VERSION 5.8 ;
BUSBITCHARS "[]" ;
DIVIDERCHAR "/" ;
UNITS
    DATABASE MICRONS 1000 ;
END UNITS

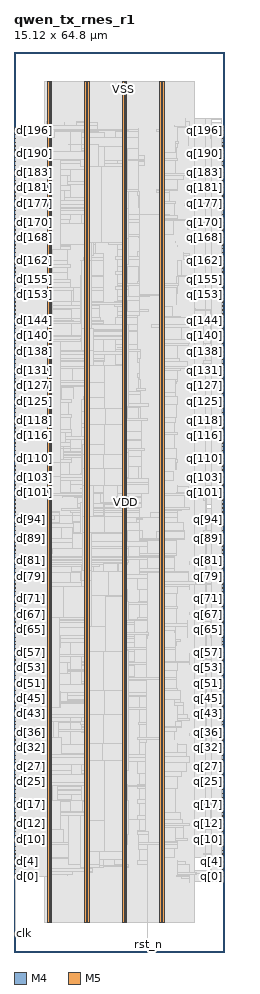
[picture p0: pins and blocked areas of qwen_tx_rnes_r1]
MACRO qwen_tx_rnes_r1
  FOREIGN qwen_tx_rnes_r1 0 0 ;
  CLASS BLOCK ;
  SIZE 15.12 BY 64.8 ;
  PIN clk
    DIRECTION INPUT ;
    USE SIGNAL ;
    PORT
      LAYER M4 ;
        RECT  0.054 1.296 0.138 1.32 ;
    END
    PORT
      LAYER M4 ;
        RECT  0.108 1.296 0.227 1.416 ;
    END
  END clk
  PIN d[0]
    DIRECTION INPUT ;
    USE SIGNAL ;
    PORT
      LAYER M4 ;
        RECT  0.054 5.424 0.138 5.448 ;
    END
  END d[0]
  PIN d[100]
    DIRECTION INPUT ;
    USE SIGNAL ;
    PORT
      LAYER M4 ;
        RECT  0.054 32.784 0.138 32.808 ;
    END
  END d[100]
  PIN d[101]
    DIRECTION INPUT ;
    USE SIGNAL ;
    PORT
      LAYER M4 ;
        RECT  0.054 33.072 0.138 33.096 ;
    END
  END d[101]
  PIN d[102]
    DIRECTION INPUT ;
    USE SIGNAL ;
    PORT
      LAYER M4 ;
        RECT  0.054 33.36 0.138 33.384 ;
    END
  END d[102]
  PIN d[103]
    DIRECTION INPUT ;
    USE SIGNAL ;
    PORT
      LAYER M4 ;
        RECT  0.054 33.6 0.138 33.624 ;
    END
  END d[103]
  PIN d[104]
    DIRECTION INPUT ;
    USE SIGNAL ;
    PORT
      LAYER M4 ;
        RECT  0.054 33.888 0.138 33.912 ;
    END
  END d[104]
  PIN d[105]
    DIRECTION INPUT ;
    USE SIGNAL ;
    PORT
      LAYER M4 ;
        RECT  0.054 34.176 0.138 34.2 ;
    END
  END d[105]
  PIN d[106]
    DIRECTION INPUT ;
    USE SIGNAL ;
    PORT
      LAYER M4 ;
        RECT  0.054 34.464 0.138 34.488 ;
    END
  END d[106]
  PIN d[107]
    DIRECTION INPUT ;
    USE SIGNAL ;
    PORT
      LAYER M4 ;
        RECT  0.054 34.704 0.138 34.728 ;
    END
  END d[107]
  PIN d[108]
    DIRECTION INPUT ;
    USE SIGNAL ;
    PORT
      LAYER M4 ;
        RECT  0.054 34.992 0.138 35.016 ;
    END
  END d[108]
  PIN d[109]
    DIRECTION INPUT ;
    USE SIGNAL ;
    PORT
      LAYER M4 ;
        RECT  0.054 35.28 0.138 35.304 ;
    END
  END d[109]
  PIN d[10]
    DIRECTION INPUT ;
    USE SIGNAL ;
    PORT
      LAYER M4 ;
        RECT  0.054 8.112 0.138 8.136 ;
    END
  END d[10]
  PIN d[110]
    DIRECTION INPUT ;
    USE SIGNAL ;
    PORT
      LAYER M4 ;
        RECT  0.054 35.52 0.138 35.544 ;
    END
  END d[110]
  PIN d[111]
    DIRECTION INPUT ;
    USE SIGNAL ;
    PORT
      LAYER M4 ;
        RECT  0.054 35.808 0.138 35.832 ;
    END
  END d[111]
  PIN d[112]
    DIRECTION INPUT ;
    USE SIGNAL ;
    PORT
      LAYER M4 ;
        RECT  0.054 36.096 0.138 36.12 ;
    END
  END d[112]
  PIN d[113]
    DIRECTION INPUT ;
    USE SIGNAL ;
    PORT
      LAYER M4 ;
        RECT  0.054 36.384 0.138 36.408 ;
    END
  END d[113]
  PIN d[114]
    DIRECTION INPUT ;
    USE SIGNAL ;
    PORT
      LAYER M4 ;
        RECT  0.054 36.624 0.138 36.648 ;
    END
  END d[114]
  PIN d[115]
    DIRECTION INPUT ;
    USE SIGNAL ;
    PORT
      LAYER M4 ;
        RECT  0.054 36.912 0.138 36.936 ;
    END
  END d[115]
  PIN d[116]
    DIRECTION INPUT ;
    USE SIGNAL ;
    PORT
      LAYER M4 ;
        RECT  0.054 37.2 0.138 37.224 ;
    END
  END d[116]
  PIN d[117]
    DIRECTION INPUT ;
    USE SIGNAL ;
    PORT
      LAYER M4 ;
        RECT  0.054 37.44 0.138 37.464 ;
    END
  END d[117]
  PIN d[118]
    DIRECTION INPUT ;
    USE SIGNAL ;
    PORT
      LAYER M4 ;
        RECT  0.054 37.728 0.138 37.752 ;
    END
  END d[118]
  PIN d[119]
    DIRECTION INPUT ;
    USE SIGNAL ;
    PORT
      LAYER M4 ;
        RECT  0.054 38.016 0.138 38.04 ;
    END
  END d[119]
  PIN d[11]
    DIRECTION INPUT ;
    USE SIGNAL ;
    PORT
      LAYER M4 ;
        RECT  0.054 8.4 0.138 8.424 ;
    END
  END d[11]
  PIN d[120]
    DIRECTION INPUT ;
    USE SIGNAL ;
    PORT
      LAYER M4 ;
        RECT  0.054 38.304 0.138 38.328 ;
    END
  END d[120]
  PIN d[121]
    DIRECTION INPUT ;
    USE SIGNAL ;
    PORT
      LAYER M4 ;
        RECT  0.054 38.544 0.138 38.568 ;
    END
  END d[121]
  PIN d[122]
    DIRECTION INPUT ;
    USE SIGNAL ;
    PORT
      LAYER M4 ;
        RECT  0.054 38.832 0.138 38.856 ;
    END
  END d[122]
  PIN d[123]
    DIRECTION INPUT ;
    USE SIGNAL ;
    PORT
      LAYER M4 ;
        RECT  0.054 39.12 0.138 39.144 ;
    END
  END d[123]
  PIN d[124]
    DIRECTION INPUT ;
    USE SIGNAL ;
    PORT
      LAYER M4 ;
        RECT  0.054 39.36 0.138 39.384 ;
    END
  END d[124]
  PIN d[125]
    DIRECTION INPUT ;
    USE SIGNAL ;
    PORT
      LAYER M4 ;
        RECT  0.054 39.648 0.138 39.672 ;
    END
  END d[125]
  PIN d[126]
    DIRECTION INPUT ;
    USE SIGNAL ;
    PORT
      LAYER M4 ;
        RECT  0.054 39.936 0.138 39.96 ;
    END
  END d[126]
  PIN d[127]
    DIRECTION INPUT ;
    USE SIGNAL ;
    PORT
      LAYER M4 ;
        RECT  0.054 40.224 0.138 40.248 ;
    END
  END d[127]
  PIN d[128]
    DIRECTION INPUT ;
    USE SIGNAL ;
    PORT
      LAYER M4 ;
        RECT  0.054 40.464 0.138 40.488 ;
    END
  END d[128]
  PIN d[129]
    DIRECTION INPUT ;
    USE SIGNAL ;
    PORT
      LAYER M4 ;
        RECT  0.054 40.752 0.138 40.776 ;
    END
  END d[129]
  PIN d[12]
    DIRECTION INPUT ;
    USE SIGNAL ;
    PORT
      LAYER M4 ;
        RECT  0.054 8.688 0.138 8.712 ;
    END
  END d[12]
  PIN d[130]
    DIRECTION INPUT ;
    USE SIGNAL ;
    PORT
      LAYER M4 ;
        RECT  0.054 41.04 0.138 41.064 ;
    END
  END d[130]
  PIN d[131]
    DIRECTION INPUT ;
    USE SIGNAL ;
    PORT
      LAYER M4 ;
        RECT  0.054 41.28 0.138 41.304 ;
    END
  END d[131]
  PIN d[132]
    DIRECTION INPUT ;
    USE SIGNAL ;
    PORT
      LAYER M4 ;
        RECT  0.054 41.568 0.138 41.592 ;
    END
  END d[132]
  PIN d[133]
    DIRECTION INPUT ;
    USE SIGNAL ;
    PORT
      LAYER M4 ;
        RECT  0.054 41.856 0.138 41.88 ;
    END
  END d[133]
  PIN d[134]
    DIRECTION INPUT ;
    USE SIGNAL ;
    PORT
      LAYER M4 ;
        RECT  0.054 42.096 0.138 42.12 ;
    END
  END d[134]
  PIN d[135]
    DIRECTION INPUT ;
    USE SIGNAL ;
    PORT
      LAYER M4 ;
        RECT  0.054 42.384 0.138 42.408 ;
    END
  END d[135]
  PIN d[136]
    DIRECTION INPUT ;
    USE SIGNAL ;
    PORT
      LAYER M4 ;
        RECT  0.054 42.672 0.138 42.696 ;
    END
  END d[136]
  PIN d[137]
    DIRECTION INPUT ;
    USE SIGNAL ;
    PORT
      LAYER M4 ;
        RECT  0.054 42.96 0.138 42.984 ;
    END
  END d[137]
  PIN d[138]
    DIRECTION INPUT ;
    USE SIGNAL ;
    PORT
      LAYER M4 ;
        RECT  0.054 43.2 0.138 43.224 ;
    END
  END d[138]
  PIN d[139]
    DIRECTION INPUT ;
    USE SIGNAL ;
    PORT
      LAYER M4 ;
        RECT  0.054 43.488 0.138 43.512 ;
    END
  END d[139]
  PIN d[13]
    DIRECTION INPUT ;
    USE SIGNAL ;
    PORT
      LAYER M4 ;
        RECT  0.054 8.928 0.138 8.952 ;
    END
  END d[13]
  PIN d[140]
    DIRECTION INPUT ;
    USE SIGNAL ;
    PORT
      LAYER M4 ;
        RECT  0.054 43.776 0.138 43.8 ;
    END
  END d[140]
  PIN d[141]
    DIRECTION INPUT ;
    USE SIGNAL ;
    PORT
      LAYER M4 ;
        RECT  0.054 44.016 0.138 44.04 ;
    END
  END d[141]
  PIN d[142]
    DIRECTION INPUT ;
    USE SIGNAL ;
    PORT
      LAYER M4 ;
        RECT  0.054 44.304 0.138 44.328 ;
    END
  END d[142]
  PIN d[143]
    DIRECTION INPUT ;
    USE SIGNAL ;
    PORT
      LAYER M4 ;
        RECT  0.054 44.592 0.138 44.616 ;
    END
  END d[143]
  PIN d[144]
    DIRECTION INPUT ;
    USE SIGNAL ;
    PORT
      LAYER M4 ;
        RECT  0.054 44.88 0.138 44.904 ;
    END
  END d[144]
  PIN d[145]
    DIRECTION INPUT ;
    USE SIGNAL ;
    PORT
      LAYER M4 ;
        RECT  0.054 45.12 0.138 45.144 ;
    END
  END d[145]
  PIN d[146]
    DIRECTION INPUT ;
    USE SIGNAL ;
    PORT
      LAYER M4 ;
        RECT  0.054 45.408 0.138 45.432 ;
    END
  END d[146]
  PIN d[147]
    DIRECTION INPUT ;
    USE SIGNAL ;
    PORT
      LAYER M4 ;
        RECT  0.054 45.696 0.138 45.72 ;
    END
  END d[147]
  PIN d[148]
    DIRECTION INPUT ;
    USE SIGNAL ;
    PORT
      LAYER M4 ;
        RECT  0.054 45.936 0.138 45.96 ;
    END
  END d[148]
  PIN d[149]
    DIRECTION INPUT ;
    USE SIGNAL ;
    PORT
      LAYER M4 ;
        RECT  0.054 46.224 0.138 46.248 ;
    END
  END d[149]
  PIN d[14]
    DIRECTION INPUT ;
    USE SIGNAL ;
    PORT
      LAYER M4 ;
        RECT  0.054 9.216 0.138 9.24 ;
    END
  END d[14]
  PIN d[150]
    DIRECTION INPUT ;
    USE SIGNAL ;
    PORT
      LAYER M4 ;
        RECT  0.054 46.512 0.138 46.536 ;
    END
  END d[150]
  PIN d[151]
    DIRECTION INPUT ;
    USE SIGNAL ;
    PORT
      LAYER M4 ;
        RECT  0.054 46.8 0.138 46.824 ;
    END
  END d[151]
  PIN d[152]
    DIRECTION INPUT ;
    USE SIGNAL ;
    PORT
      LAYER M4 ;
        RECT  0.054 47.04 0.138 47.064 ;
    END
  END d[152]
  PIN d[153]
    DIRECTION INPUT ;
    USE SIGNAL ;
    PORT
      LAYER M4 ;
        RECT  0.054 47.328 0.138 47.352 ;
    END
  END d[153]
  PIN d[154]
    DIRECTION INPUT ;
    USE SIGNAL ;
    PORT
      LAYER M4 ;
        RECT  0.054 47.616 0.138 47.64 ;
    END
  END d[154]
  PIN d[155]
    DIRECTION INPUT ;
    USE SIGNAL ;
    PORT
      LAYER M4 ;
        RECT  0.054 47.856 0.138 47.88 ;
    END
  END d[155]
  PIN d[156]
    DIRECTION INPUT ;
    USE SIGNAL ;
    PORT
      LAYER M4 ;
        RECT  0.054 48.144 0.138 48.168 ;
    END
  END d[156]
  PIN d[157]
    DIRECTION INPUT ;
    USE SIGNAL ;
    PORT
      LAYER M4 ;
        RECT  0.054 48.432 0.138 48.456 ;
    END
  END d[157]
  PIN d[158]
    DIRECTION INPUT ;
    USE SIGNAL ;
    PORT
      LAYER M4 ;
        RECT  0.054 48.72 0.138 48.744 ;
    END
  END d[158]
  PIN d[159]
    DIRECTION INPUT ;
    USE SIGNAL ;
    PORT
      LAYER M4 ;
        RECT  0.054 48.96 0.138 48.984 ;
    END
  END d[159]
  PIN d[15]
    DIRECTION INPUT ;
    USE SIGNAL ;
    PORT
      LAYER M4 ;
        RECT  0.054 9.504 0.138 9.528 ;
    END
  END d[15]
  PIN d[160]
    DIRECTION INPUT ;
    USE SIGNAL ;
    PORT
      LAYER M4 ;
        RECT  0.054 49.248 0.138 49.272 ;
    END
  END d[160]
  PIN d[161]
    DIRECTION INPUT ;
    USE SIGNAL ;
    PORT
      LAYER M4 ;
        RECT  0.054 49.536 0.138 49.56 ;
    END
  END d[161]
  PIN d[162]
    DIRECTION INPUT ;
    USE SIGNAL ;
    PORT
      LAYER M4 ;
        RECT  0.054 49.776 0.138 49.8 ;
    END
  END d[162]
  PIN d[163]
    DIRECTION INPUT ;
    USE SIGNAL ;
    PORT
      LAYER M4 ;
        RECT  0.054 50.064 0.138 50.088 ;
    END
  END d[163]
  PIN d[164]
    DIRECTION INPUT ;
    USE SIGNAL ;
    PORT
      LAYER M4 ;
        RECT  0.054 50.352 0.138 50.376 ;
    END
  END d[164]
  PIN d[165]
    DIRECTION INPUT ;
    USE SIGNAL ;
    PORT
      LAYER M4 ;
        RECT  0.054 50.64 0.138 50.664 ;
    END
  END d[165]
  PIN d[166]
    DIRECTION INPUT ;
    USE SIGNAL ;
    PORT
      LAYER M4 ;
        RECT  0.054 50.88 0.138 50.904 ;
    END
  END d[166]
  PIN d[167]
    DIRECTION INPUT ;
    USE SIGNAL ;
    PORT
      LAYER M4 ;
        RECT  0.054 51.168 0.138 51.192 ;
    END
  END d[167]
  PIN d[168]
    DIRECTION INPUT ;
    USE SIGNAL ;
    PORT
      LAYER M4 ;
        RECT  0.054 51.456 0.138 51.48 ;
    END
  END d[168]
  PIN d[169]
    DIRECTION INPUT ;
    USE SIGNAL ;
    PORT
      LAYER M4 ;
        RECT  0.054 51.696 0.138 51.72 ;
    END
  END d[169]
  PIN d[16]
    DIRECTION INPUT ;
    USE SIGNAL ;
    PORT
      LAYER M4 ;
        RECT  0.054 9.792 0.138 9.816 ;
    END
  END d[16]
  PIN d[170]
    DIRECTION INPUT ;
    USE SIGNAL ;
    PORT
      LAYER M4 ;
        RECT  0.054 51.984 0.138 52.008 ;
    END
  END d[170]
  PIN d[171]
    DIRECTION INPUT ;
    USE SIGNAL ;
    PORT
      LAYER M4 ;
        RECT  0.054 52.272 0.138 52.296 ;
    END
  END d[171]
  PIN d[172]
    DIRECTION INPUT ;
    USE SIGNAL ;
    PORT
      LAYER M4 ;
        RECT  0.054 52.512 0.138 52.536 ;
    END
  END d[172]
  PIN d[173]
    DIRECTION INPUT ;
    USE SIGNAL ;
    PORT
      LAYER M4 ;
        RECT  0.054 52.8 0.138 52.824 ;
    END
  END d[173]
  PIN d[174]
    DIRECTION INPUT ;
    USE SIGNAL ;
    PORT
      LAYER M4 ;
        RECT  0.054 53.088 0.138 53.112 ;
    END
  END d[174]
  PIN d[175]
    DIRECTION INPUT ;
    USE SIGNAL ;
    PORT
      LAYER M4 ;
        RECT  0.054 53.376 0.138 53.4 ;
    END
  END d[175]
  PIN d[176]
    DIRECTION INPUT ;
    USE SIGNAL ;
    PORT
      LAYER M4 ;
        RECT  0.054 53.616 0.138 53.64 ;
    END
  END d[176]
  PIN d[177]
    DIRECTION INPUT ;
    USE SIGNAL ;
    PORT
      LAYER M4 ;
        RECT  0.054 53.904 0.138 53.928 ;
    END
  END d[177]
  PIN d[178]
    DIRECTION INPUT ;
    USE SIGNAL ;
    PORT
      LAYER M4 ;
        RECT  0.054 54.192 0.138 54.216 ;
    END
  END d[178]
  PIN d[179]
    DIRECTION INPUT ;
    USE SIGNAL ;
    PORT
      LAYER M4 ;
        RECT  0.054 54.432 0.138 54.456 ;
    END
  END d[179]
  PIN d[17]
    DIRECTION INPUT ;
    USE SIGNAL ;
    PORT
      LAYER M4 ;
        RECT  0.054 10.032 0.138 10.056 ;
    END
  END d[17]
  PIN d[180]
    DIRECTION INPUT ;
    USE SIGNAL ;
    PORT
      LAYER M4 ;
        RECT  0.054 54.72 0.138 54.744 ;
    END
  END d[180]
  PIN d[181]
    DIRECTION INPUT ;
    USE SIGNAL ;
    PORT
      LAYER M4 ;
        RECT  0.054 55.008 0.138 55.032 ;
    END
  END d[181]
  PIN d[182]
    DIRECTION INPUT ;
    USE SIGNAL ;
    PORT
      LAYER M4 ;
        RECT  0.054 55.296 0.138 55.32 ;
    END
  END d[182]
  PIN d[183]
    DIRECTION INPUT ;
    USE SIGNAL ;
    PORT
      LAYER M4 ;
        RECT  0.054 55.536 0.138 55.56 ;
    END
  END d[183]
  PIN d[184]
    DIRECTION INPUT ;
    USE SIGNAL ;
    PORT
      LAYER M4 ;
        RECT  0.054 55.824 0.138 55.848 ;
    END
  END d[184]
  PIN d[185]
    DIRECTION INPUT ;
    USE SIGNAL ;
    PORT
      LAYER M4 ;
        RECT  0.054 56.112 0.138 56.136 ;
    END
  END d[185]
  PIN d[186]
    DIRECTION INPUT ;
    USE SIGNAL ;
    PORT
      LAYER M4 ;
        RECT  0.054 56.352 0.138 56.376 ;
    END
  END d[186]
  PIN d[187]
    DIRECTION INPUT ;
    USE SIGNAL ;
    PORT
      LAYER M4 ;
        RECT  0.054 56.64 0.138 56.664 ;
    END
  END d[187]
  PIN d[188]
    DIRECTION INPUT ;
    USE SIGNAL ;
    PORT
      LAYER M4 ;
        RECT  0.054 56.928 0.138 56.952 ;
    END
  END d[188]
  PIN d[189]
    DIRECTION INPUT ;
    USE SIGNAL ;
    PORT
      LAYER M4 ;
        RECT  0.054 57.216 0.138 57.24 ;
    END
  END d[189]
  PIN d[18]
    DIRECTION INPUT ;
    USE SIGNAL ;
    PORT
      LAYER M4 ;
        RECT  0.054 10.32 0.138 10.344 ;
    END
  END d[18]
  PIN d[190]
    DIRECTION INPUT ;
    USE SIGNAL ;
    PORT
      LAYER M4 ;
        RECT  0.054 57.456 0.138 57.48 ;
    END
  END d[190]
  PIN d[191]
    DIRECTION INPUT ;
    USE SIGNAL ;
    PORT
      LAYER M4 ;
        RECT  0.054 57.744 0.138 57.768 ;
    END
  END d[191]
  PIN d[192]
    DIRECTION INPUT ;
    USE SIGNAL ;
    PORT
      LAYER M4 ;
        RECT  0.054 58.032 0.138 58.056 ;
    END
  END d[192]
  PIN d[193]
    DIRECTION INPUT ;
    USE SIGNAL ;
    PORT
      LAYER M4 ;
        RECT  0.054 58.272 0.138 58.296 ;
    END
  END d[193]
  PIN d[194]
    DIRECTION INPUT ;
    USE SIGNAL ;
    PORT
      LAYER M4 ;
        RECT  0.054 58.56 0.138 58.584 ;
    END
  END d[194]
  PIN d[195]
    DIRECTION INPUT ;
    USE SIGNAL ;
    PORT
      LAYER M4 ;
        RECT  0.054 58.848 0.138 58.872 ;
    END
  END d[195]
  PIN d[196]
    DIRECTION INPUT ;
    USE SIGNAL ;
    PORT
      LAYER M4 ;
        RECT  0.054 59.136 0.138 59.16 ;
    END
  END d[196]
  PIN d[197]
    DIRECTION INPUT ;
    USE SIGNAL ;
    PORT
      LAYER M4 ;
        RECT  0.054 59.376 0.138 59.4 ;
    END
  END d[197]
  PIN d[19]
    DIRECTION INPUT ;
    USE SIGNAL ;
    PORT
      LAYER M4 ;
        RECT  0.054 10.608 0.138 10.632 ;
    END
  END d[19]
  PIN d[1]
    DIRECTION INPUT ;
    USE SIGNAL ;
    PORT
      LAYER M4 ;
        RECT  0.054 5.664 0.138 5.688 ;
    END
  END d[1]
  PIN d[20]
    DIRECTION INPUT ;
    USE SIGNAL ;
    PORT
      LAYER M4 ;
        RECT  0.054 10.848 0.138 10.872 ;
    END
  END d[20]
  PIN d[21]
    DIRECTION INPUT ;
    USE SIGNAL ;
    PORT
      LAYER M4 ;
        RECT  0.054 11.136 0.138 11.16 ;
    END
  END d[21]
  PIN d[22]
    DIRECTION INPUT ;
    USE SIGNAL ;
    PORT
      LAYER M4 ;
        RECT  0.054 11.424 0.138 11.448 ;
    END
  END d[22]
  PIN d[23]
    DIRECTION INPUT ;
    USE SIGNAL ;
    PORT
      LAYER M4 ;
        RECT  0.054 11.712 0.138 11.736 ;
    END
  END d[23]
  PIN d[24]
    DIRECTION INPUT ;
    USE SIGNAL ;
    PORT
      LAYER M4 ;
        RECT  0.054 11.952 0.138 11.976 ;
    END
  END d[24]
  PIN d[25]
    DIRECTION INPUT ;
    USE SIGNAL ;
    PORT
      LAYER M4 ;
        RECT  0.054 12.24 0.138 12.264 ;
    END
  END d[25]
  PIN d[26]
    DIRECTION INPUT ;
    USE SIGNAL ;
    PORT
      LAYER M4 ;
        RECT  0.054 12.528 0.138 12.552 ;
    END
  END d[26]
  PIN d[27]
    DIRECTION INPUT ;
    USE SIGNAL ;
    PORT
      LAYER M4 ;
        RECT  0.054 12.768 0.138 12.792 ;
    END
  END d[27]
  PIN d[28]
    DIRECTION INPUT ;
    USE SIGNAL ;
    PORT
      LAYER M4 ;
        RECT  0.054 13.056 0.138 13.08 ;
    END
  END d[28]
  PIN d[29]
    DIRECTION INPUT ;
    USE SIGNAL ;
    PORT
      LAYER M4 ;
        RECT  0.054 13.344 0.138 13.368 ;
    END
  END d[29]
  PIN d[2]
    DIRECTION INPUT ;
    USE SIGNAL ;
    PORT
      LAYER M4 ;
        RECT  0.054 5.952 0.138 5.976 ;
    END
  END d[2]
  PIN d[30]
    DIRECTION INPUT ;
    USE SIGNAL ;
    PORT
      LAYER M4 ;
        RECT  0.054 13.632 0.138 13.656 ;
    END
  END d[30]
  PIN d[31]
    DIRECTION INPUT ;
    USE SIGNAL ;
    PORT
      LAYER M4 ;
        RECT  0.054 13.872 0.138 13.896 ;
    END
  END d[31]
  PIN d[32]
    DIRECTION INPUT ;
    USE SIGNAL ;
    PORT
      LAYER M4 ;
        RECT  0.054 14.16 0.138 14.184 ;
    END
  END d[32]
  PIN d[33]
    DIRECTION INPUT ;
    USE SIGNAL ;
    PORT
      LAYER M4 ;
        RECT  0.054 14.448 0.138 14.472 ;
    END
  END d[33]
  PIN d[34]
    DIRECTION INPUT ;
    USE SIGNAL ;
    PORT
      LAYER M4 ;
        RECT  0.054 14.688 0.138 14.712 ;
    END
  END d[34]
  PIN d[35]
    DIRECTION INPUT ;
    USE SIGNAL ;
    PORT
      LAYER M4 ;
        RECT  0.054 14.976 0.138 15 ;
    END
  END d[35]
  PIN d[36]
    DIRECTION INPUT ;
    USE SIGNAL ;
    PORT
      LAYER M4 ;
        RECT  0.054 15.264 0.138 15.288 ;
    END
  END d[36]
  PIN d[37]
    DIRECTION INPUT ;
    USE SIGNAL ;
    PORT
      LAYER M4 ;
        RECT  0.054 15.552 0.138 15.576 ;
    END
  END d[37]
  PIN d[38]
    DIRECTION INPUT ;
    USE SIGNAL ;
    PORT
      LAYER M4 ;
        RECT  0.054 15.792 0.138 15.816 ;
    END
  END d[38]
  PIN d[39]
    DIRECTION INPUT ;
    USE SIGNAL ;
    PORT
      LAYER M4 ;
        RECT  0.054 16.08 0.138 16.104 ;
    END
  END d[39]
  PIN d[3]
    DIRECTION INPUT ;
    USE SIGNAL ;
    PORT
      LAYER M4 ;
        RECT  0.054 6.192 0.138 6.216 ;
    END
  END d[3]
  PIN d[40]
    DIRECTION INPUT ;
    USE SIGNAL ;
    PORT
      LAYER M4 ;
        RECT  0.054 16.368 0.138 16.392 ;
    END
  END d[40]
  PIN d[41]
    DIRECTION INPUT ;
    USE SIGNAL ;
    PORT
      LAYER M4 ;
        RECT  0.054 16.608 0.138 16.632 ;
    END
  END d[41]
  PIN d[42]
    DIRECTION INPUT ;
    USE SIGNAL ;
    PORT
      LAYER M4 ;
        RECT  0.054 16.896 0.138 16.92 ;
    END
  END d[42]
  PIN d[43]
    DIRECTION INPUT ;
    USE SIGNAL ;
    PORT
      LAYER M4 ;
        RECT  0.054 17.184 0.138 17.208 ;
    END
  END d[43]
  PIN d[44]
    DIRECTION INPUT ;
    USE SIGNAL ;
    PORT
      LAYER M4 ;
        RECT  0.054 17.472 0.138 17.496 ;
    END
  END d[44]
  PIN d[45]
    DIRECTION INPUT ;
    USE SIGNAL ;
    PORT
      LAYER M4 ;
        RECT  0.054 17.712 0.138 17.736 ;
    END
  END d[45]
  PIN d[46]
    DIRECTION INPUT ;
    USE SIGNAL ;
    PORT
      LAYER M4 ;
        RECT  0.054 18 0.138 18.024 ;
    END
  END d[46]
  PIN d[47]
    DIRECTION INPUT ;
    USE SIGNAL ;
    PORT
      LAYER M4 ;
        RECT  0.054 18.288 0.138 18.312 ;
    END
  END d[47]
  PIN d[48]
    DIRECTION INPUT ;
    USE SIGNAL ;
    PORT
      LAYER M4 ;
        RECT  0.054 18.528 0.138 18.552 ;
    END
  END d[48]
  PIN d[49]
    DIRECTION INPUT ;
    USE SIGNAL ;
    PORT
      LAYER M4 ;
        RECT  0.054 18.816 0.138 18.84 ;
    END
  END d[49]
  PIN d[4]
    DIRECTION INPUT ;
    USE SIGNAL ;
    PORT
      LAYER M4 ;
        RECT  0.054 6.48 0.138 6.504 ;
    END
  END d[4]
  PIN d[50]
    DIRECTION INPUT ;
    USE SIGNAL ;
    PORT
      LAYER M4 ;
        RECT  0.054 19.104 0.138 19.128 ;
    END
  END d[50]
  PIN d[51]
    DIRECTION INPUT ;
    USE SIGNAL ;
    PORT
      LAYER M4 ;
        RECT  0.054 19.344 0.138 19.368 ;
    END
  END d[51]
  PIN d[52]
    DIRECTION INPUT ;
    USE SIGNAL ;
    PORT
      LAYER M4 ;
        RECT  0.054 19.632 0.138 19.656 ;
    END
  END d[52]
  PIN d[53]
    DIRECTION INPUT ;
    USE SIGNAL ;
    PORT
      LAYER M4 ;
        RECT  0.054 19.92 0.138 19.944 ;
    END
  END d[53]
  PIN d[54]
    DIRECTION INPUT ;
    USE SIGNAL ;
    PORT
      LAYER M4 ;
        RECT  0.054 20.208 0.138 20.232 ;
    END
  END d[54]
  PIN d[55]
    DIRECTION INPUT ;
    USE SIGNAL ;
    PORT
      LAYER M4 ;
        RECT  0.054 20.448 0.138 20.472 ;
    END
  END d[55]
  PIN d[56]
    DIRECTION INPUT ;
    USE SIGNAL ;
    PORT
      LAYER M4 ;
        RECT  0.054 20.736 0.138 20.76 ;
    END
  END d[56]
  PIN d[57]
    DIRECTION INPUT ;
    USE SIGNAL ;
    PORT
      LAYER M4 ;
        RECT  0.054 21.024 0.138 21.048 ;
    END
  END d[57]
  PIN d[58]
    DIRECTION INPUT ;
    USE SIGNAL ;
    PORT
      LAYER M4 ;
        RECT  0.054 21.264 0.138 21.288 ;
    END
  END d[58]
  PIN d[59]
    DIRECTION INPUT ;
    USE SIGNAL ;
    PORT
      LAYER M4 ;
        RECT  0.054 21.552 0.138 21.576 ;
    END
  END d[59]
  PIN d[5]
    DIRECTION INPUT ;
    USE SIGNAL ;
    PORT
      LAYER M4 ;
        RECT  0.054 6.768 0.138 6.792 ;
    END
  END d[5]
  PIN d[60]
    DIRECTION INPUT ;
    USE SIGNAL ;
    PORT
      LAYER M4 ;
        RECT  0.054 21.84 0.138 21.864 ;
    END
  END d[60]
  PIN d[61]
    DIRECTION INPUT ;
    USE SIGNAL ;
    PORT
      LAYER M4 ;
        RECT  0.054 22.128 0.138 22.152 ;
    END
  END d[61]
  PIN d[62]
    DIRECTION INPUT ;
    USE SIGNAL ;
    PORT
      LAYER M4 ;
        RECT  0.054 22.368 0.138 22.392 ;
    END
  END d[62]
  PIN d[63]
    DIRECTION INPUT ;
    USE SIGNAL ;
    PORT
      LAYER M4 ;
        RECT  0.054 22.656 0.138 22.68 ;
    END
  END d[63]
  PIN d[64]
    DIRECTION INPUT ;
    USE SIGNAL ;
    PORT
      LAYER M4 ;
        RECT  0.054 22.944 0.138 22.968 ;
    END
  END d[64]
  PIN d[65]
    DIRECTION INPUT ;
    USE SIGNAL ;
    PORT
      LAYER M4 ;
        RECT  0.054 23.184 0.138 23.208 ;
    END
  END d[65]
  PIN d[66]
    DIRECTION INPUT ;
    USE SIGNAL ;
    PORT
      LAYER M4 ;
        RECT  0.054 23.472 0.138 23.496 ;
    END
  END d[66]
  PIN d[67]
    DIRECTION INPUT ;
    USE SIGNAL ;
    PORT
      LAYER M4 ;
        RECT  0.054 23.76 0.138 23.784 ;
    END
  END d[67]
  PIN d[68]
    DIRECTION INPUT ;
    USE SIGNAL ;
    PORT
      LAYER M4 ;
        RECT  0.054 24.048 0.138 24.072 ;
    END
  END d[68]
  PIN d[69]
    DIRECTION INPUT ;
    USE SIGNAL ;
    PORT
      LAYER M4 ;
        RECT  0.054 24.288 0.138 24.312 ;
    END
  END d[69]
  PIN d[6]
    DIRECTION INPUT ;
    USE SIGNAL ;
    PORT
      LAYER M4 ;
        RECT  0.054 7.056 0.138 7.08 ;
    END
  END d[6]
  PIN d[70]
    DIRECTION INPUT ;
    USE SIGNAL ;
    PORT
      LAYER M4 ;
        RECT  0.054 24.576 0.138 24.6 ;
    END
  END d[70]
  PIN d[71]
    DIRECTION INPUT ;
    USE SIGNAL ;
    PORT
      LAYER M4 ;
        RECT  0.054 24.864 0.138 24.888 ;
    END
  END d[71]
  PIN d[72]
    DIRECTION INPUT ;
    USE SIGNAL ;
    PORT
      LAYER M4 ;
        RECT  0.054 25.104 0.138 25.128 ;
    END
  END d[72]
  PIN d[73]
    DIRECTION INPUT ;
    USE SIGNAL ;
    PORT
      LAYER M4 ;
        RECT  0.054 25.392 0.138 25.416 ;
    END
  END d[73]
  PIN d[74]
    DIRECTION INPUT ;
    USE SIGNAL ;
    PORT
      LAYER M4 ;
        RECT  0.054 25.68 0.138 25.704 ;
    END
  END d[74]
  PIN d[75]
    DIRECTION INPUT ;
    USE SIGNAL ;
    PORT
      LAYER M4 ;
        RECT  0.054 25.968 0.138 25.992 ;
    END
  END d[75]
  PIN d[76]
    DIRECTION INPUT ;
    USE SIGNAL ;
    PORT
      LAYER M4 ;
        RECT  0.054 26.208 0.138 26.232 ;
    END
  END d[76]
  PIN d[77]
    DIRECTION INPUT ;
    USE SIGNAL ;
    PORT
      LAYER M4 ;
        RECT  0.054 26.496 0.138 26.52 ;
    END
  END d[77]
  PIN d[78]
    DIRECTION INPUT ;
    USE SIGNAL ;
    PORT
      LAYER M4 ;
        RECT  0.054 26.784 0.138 26.808 ;
    END
  END d[78]
  PIN d[79]
    DIRECTION INPUT ;
    USE SIGNAL ;
    PORT
      LAYER M4 ;
        RECT  0.054 27.024 0.138 27.048 ;
    END
  END d[79]
  PIN d[7]
    DIRECTION INPUT ;
    USE SIGNAL ;
    PORT
      LAYER M4 ;
        RECT  0.054 7.296 0.138 7.32 ;
    END
  END d[7]
  PIN d[80]
    DIRECTION INPUT ;
    USE SIGNAL ;
    PORT
      LAYER M4 ;
        RECT  0.054 27.312 0.138 27.336 ;
    END
  END d[80]
  PIN d[81]
    DIRECTION INPUT ;
    USE SIGNAL ;
    PORT
      LAYER M4 ;
        RECT  0.054 27.6 0.138 27.624 ;
    END
  END d[81]
  PIN d[82]
    DIRECTION INPUT ;
    USE SIGNAL ;
    PORT
      LAYER M4 ;
        RECT  0.054 27.888 0.138 27.912 ;
    END
  END d[82]
  PIN d[83]
    DIRECTION INPUT ;
    USE SIGNAL ;
    PORT
      LAYER M4 ;
        RECT  0.054 28.128 0.138 28.152 ;
    END
  END d[83]
  PIN d[84]
    DIRECTION INPUT ;
    USE SIGNAL ;
    PORT
      LAYER M4 ;
        RECT  0.054 28.416 0.138 28.44 ;
    END
  END d[84]
  PIN d[85]
    DIRECTION INPUT ;
    USE SIGNAL ;
    PORT
      LAYER M4 ;
        RECT  0.054 28.704 0.138 28.728 ;
    END
  END d[85]
  PIN d[86]
    DIRECTION INPUT ;
    USE SIGNAL ;
    PORT
      LAYER M4 ;
        RECT  0.054 28.944 0.138 28.968 ;
    END
  END d[86]
  PIN d[87]
    DIRECTION INPUT ;
    USE SIGNAL ;
    PORT
      LAYER M4 ;
        RECT  0.054 29.232 0.138 29.256 ;
    END
  END d[87]
  PIN d[88]
    DIRECTION INPUT ;
    USE SIGNAL ;
    PORT
      LAYER M4 ;
        RECT  0.054 29.52 0.138 29.544 ;
    END
  END d[88]
  PIN d[89]
    DIRECTION INPUT ;
    USE SIGNAL ;
    PORT
      LAYER M4 ;
        RECT  0.054 29.76 0.138 29.784 ;
    END
  END d[89]
  PIN d[8]
    DIRECTION INPUT ;
    USE SIGNAL ;
    PORT
      LAYER M4 ;
        RECT  0.054 7.584 0.138 7.608 ;
    END
  END d[8]
  PIN d[90]
    DIRECTION INPUT ;
    USE SIGNAL ;
    PORT
      LAYER M4 ;
        RECT  0.054 30.048 0.138 30.072 ;
    END
  END d[90]
  PIN d[91]
    DIRECTION INPUT ;
    USE SIGNAL ;
    PORT
      LAYER M4 ;
        RECT  0.054 30.336 0.138 30.36 ;
    END
  END d[91]
  PIN d[92]
    DIRECTION INPUT ;
    USE SIGNAL ;
    PORT
      LAYER M4 ;
        RECT  0.054 30.624 0.138 30.648 ;
    END
  END d[92]
  PIN d[93]
    DIRECTION INPUT ;
    USE SIGNAL ;
    PORT
      LAYER M4 ;
        RECT  0.054 30.864 0.138 30.888 ;
    END
  END d[93]
  PIN d[94]
    DIRECTION INPUT ;
    USE SIGNAL ;
    PORT
      LAYER M4 ;
        RECT  0.054 31.152 0.138 31.176 ;
    END
  END d[94]
  PIN d[95]
    DIRECTION INPUT ;
    USE SIGNAL ;
    PORT
      LAYER M4 ;
        RECT  0.054 31.44 0.138 31.464 ;
    END
  END d[95]
  PIN d[96]
    DIRECTION INPUT ;
    USE SIGNAL ;
    PORT
      LAYER M4 ;
        RECT  0.054 31.68 0.138 31.704 ;
    END
  END d[96]
  PIN d[97]
    DIRECTION INPUT ;
    USE SIGNAL ;
    PORT
      LAYER M4 ;
        RECT  0.054 31.968 0.138 31.992 ;
    END
  END d[97]
  PIN d[98]
    DIRECTION INPUT ;
    USE SIGNAL ;
    PORT
      LAYER M4 ;
        RECT  0.054 32.256 0.138 32.28 ;
    END
  END d[98]
  PIN d[99]
    DIRECTION INPUT ;
    USE SIGNAL ;
    PORT
      LAYER M4 ;
        RECT  0.054 32.544 0.138 32.568 ;
    END
  END d[99]
  PIN d[9]
    DIRECTION INPUT ;
    USE SIGNAL ;
    PORT
      LAYER M4 ;
        RECT  0.054 7.872 0.138 7.896 ;
    END
  END d[9]
  PIN q[0]
    DIRECTION OUTPUT ;
    USE SIGNAL ;
    PORT
      LAYER M4 ;
        RECT  14.982 5.424 15.066 5.448 ;
    END
  END q[0]
  PIN q[100]
    DIRECTION OUTPUT ;
    USE SIGNAL ;
    PORT
      LAYER M4 ;
        RECT  14.982 32.784 15.066 32.808 ;
    END
  END q[100]
  PIN q[101]
    DIRECTION OUTPUT ;
    USE SIGNAL ;
    PORT
      LAYER M4 ;
        RECT  14.982 33.072 15.066 33.096 ;
    END
  END q[101]
  PIN q[102]
    DIRECTION OUTPUT ;
    USE SIGNAL ;
    PORT
      LAYER M4 ;
        RECT  14.982 33.36 15.066 33.384 ;
    END
  END q[102]
  PIN q[103]
    DIRECTION OUTPUT ;
    USE SIGNAL ;
    PORT
      LAYER M4 ;
        RECT  14.982 33.6 15.066 33.624 ;
    END
  END q[103]
  PIN q[104]
    DIRECTION OUTPUT ;
    USE SIGNAL ;
    PORT
      LAYER M4 ;
        RECT  14.982 33.888 15.066 33.912 ;
    END
  END q[104]
  PIN q[105]
    DIRECTION OUTPUT ;
    USE SIGNAL ;
    PORT
      LAYER M4 ;
        RECT  14.982 34.176 15.066 34.2 ;
    END
  END q[105]
  PIN q[106]
    DIRECTION OUTPUT ;
    USE SIGNAL ;
    PORT
      LAYER M4 ;
        RECT  14.982 34.464 15.066 34.488 ;
    END
  END q[106]
  PIN q[107]
    DIRECTION OUTPUT ;
    USE SIGNAL ;
    PORT
      LAYER M4 ;
        RECT  14.982 34.704 15.066 34.728 ;
    END
  END q[107]
  PIN q[108]
    DIRECTION OUTPUT ;
    USE SIGNAL ;
    PORT
      LAYER M4 ;
        RECT  14.982 34.992 15.066 35.016 ;
    END
  END q[108]
  PIN q[109]
    DIRECTION OUTPUT ;
    USE SIGNAL ;
    PORT
      LAYER M4 ;
        RECT  14.982 35.28 15.066 35.304 ;
    END
  END q[109]
  PIN q[10]
    DIRECTION OUTPUT ;
    USE SIGNAL ;
    PORT
      LAYER M4 ;
        RECT  14.982 8.112 15.066 8.136 ;
    END
  END q[10]
  PIN q[110]
    DIRECTION OUTPUT ;
    USE SIGNAL ;
    PORT
      LAYER M4 ;
        RECT  14.982 35.52 15.066 35.544 ;
    END
  END q[110]
  PIN q[111]
    DIRECTION OUTPUT ;
    USE SIGNAL ;
    PORT
      LAYER M4 ;
        RECT  14.982 35.808 15.066 35.832 ;
    END
  END q[111]
  PIN q[112]
    DIRECTION OUTPUT ;
    USE SIGNAL ;
    PORT
      LAYER M4 ;
        RECT  14.982 36.096 15.066 36.12 ;
    END
  END q[112]
  PIN q[113]
    DIRECTION OUTPUT ;
    USE SIGNAL ;
    PORT
      LAYER M4 ;
        RECT  14.982 36.384 15.066 36.408 ;
    END
  END q[113]
  PIN q[114]
    DIRECTION OUTPUT ;
    USE SIGNAL ;
    PORT
      LAYER M4 ;
        RECT  14.982 36.624 15.066 36.648 ;
    END
  END q[114]
  PIN q[115]
    DIRECTION OUTPUT ;
    USE SIGNAL ;
    PORT
      LAYER M4 ;
        RECT  14.982 36.912 15.066 36.936 ;
    END
  END q[115]
  PIN q[116]
    DIRECTION OUTPUT ;
    USE SIGNAL ;
    PORT
      LAYER M4 ;
        RECT  14.982 37.2 15.066 37.224 ;
    END
  END q[116]
  PIN q[117]
    DIRECTION OUTPUT ;
    USE SIGNAL ;
    PORT
      LAYER M4 ;
        RECT  14.982 37.44 15.066 37.464 ;
    END
  END q[117]
  PIN q[118]
    DIRECTION OUTPUT ;
    USE SIGNAL ;
    PORT
      LAYER M4 ;
        RECT  14.982 37.728 15.066 37.752 ;
    END
  END q[118]
  PIN q[119]
    DIRECTION OUTPUT ;
    USE SIGNAL ;
    PORT
      LAYER M4 ;
        RECT  14.982 38.016 15.066 38.04 ;
    END
  END q[119]
  PIN q[11]
    DIRECTION OUTPUT ;
    USE SIGNAL ;
    PORT
      LAYER M4 ;
        RECT  14.982 8.4 15.066 8.424 ;
    END
  END q[11]
  PIN q[120]
    DIRECTION OUTPUT ;
    USE SIGNAL ;
    PORT
      LAYER M4 ;
        RECT  14.982 38.304 15.066 38.328 ;
    END
  END q[120]
  PIN q[121]
    DIRECTION OUTPUT ;
    USE SIGNAL ;
    PORT
      LAYER M4 ;
        RECT  14.982 38.544 15.066 38.568 ;
    END
  END q[121]
  PIN q[122]
    DIRECTION OUTPUT ;
    USE SIGNAL ;
    PORT
      LAYER M4 ;
        RECT  14.982 38.832 15.066 38.856 ;
    END
  END q[122]
  PIN q[123]
    DIRECTION OUTPUT ;
    USE SIGNAL ;
    PORT
      LAYER M4 ;
        RECT  14.982 39.12 15.066 39.144 ;
    END
  END q[123]
  PIN q[124]
    DIRECTION OUTPUT ;
    USE SIGNAL ;
    PORT
      LAYER M4 ;
        RECT  14.982 39.36 15.066 39.384 ;
    END
  END q[124]
  PIN q[125]
    DIRECTION OUTPUT ;
    USE SIGNAL ;
    PORT
      LAYER M4 ;
        RECT  14.982 39.648 15.066 39.672 ;
    END
  END q[125]
  PIN q[126]
    DIRECTION OUTPUT ;
    USE SIGNAL ;
    PORT
      LAYER M4 ;
        RECT  14.982 39.936 15.066 39.96 ;
    END
  END q[126]
  PIN q[127]
    DIRECTION OUTPUT ;
    USE SIGNAL ;
    PORT
      LAYER M4 ;
        RECT  14.982 40.224 15.066 40.248 ;
    END
  END q[127]
  PIN q[128]
    DIRECTION OUTPUT ;
    USE SIGNAL ;
    PORT
      LAYER M4 ;
        RECT  14.982 40.464 15.066 40.488 ;
    END
  END q[128]
  PIN q[129]
    DIRECTION OUTPUT ;
    USE SIGNAL ;
    PORT
      LAYER M4 ;
        RECT  14.982 40.752 15.066 40.776 ;
    END
  END q[129]
  PIN q[12]
    DIRECTION OUTPUT ;
    USE SIGNAL ;
    PORT
      LAYER M4 ;
        RECT  14.982 8.688 15.066 8.712 ;
    END
  END q[12]
  PIN q[130]
    DIRECTION OUTPUT ;
    USE SIGNAL ;
    PORT
      LAYER M4 ;
        RECT  14.982 41.04 15.066 41.064 ;
    END
  END q[130]
  PIN q[131]
    DIRECTION OUTPUT ;
    USE SIGNAL ;
    PORT
      LAYER M4 ;
        RECT  14.982 41.28 15.066 41.304 ;
    END
  END q[131]
  PIN q[132]
    DIRECTION OUTPUT ;
    USE SIGNAL ;
    PORT
      LAYER M4 ;
        RECT  14.982 41.568 15.066 41.592 ;
    END
  END q[132]
  PIN q[133]
    DIRECTION OUTPUT ;
    USE SIGNAL ;
    PORT
      LAYER M4 ;
        RECT  14.982 41.856 15.066 41.88 ;
    END
  END q[133]
  PIN q[134]
    DIRECTION OUTPUT ;
    USE SIGNAL ;
    PORT
      LAYER M4 ;
        RECT  14.982 42.096 15.066 42.12 ;
    END
  END q[134]
  PIN q[135]
    DIRECTION OUTPUT ;
    USE SIGNAL ;
    PORT
      LAYER M4 ;
        RECT  14.982 42.384 15.066 42.408 ;
    END
  END q[135]
  PIN q[136]
    DIRECTION OUTPUT ;
    USE SIGNAL ;
    PORT
      LAYER M4 ;
        RECT  14.982 42.672 15.066 42.696 ;
    END
  END q[136]
  PIN q[137]
    DIRECTION OUTPUT ;
    USE SIGNAL ;
    PORT
      LAYER M4 ;
        RECT  14.982 42.96 15.066 42.984 ;
    END
  END q[137]
  PIN q[138]
    DIRECTION OUTPUT ;
    USE SIGNAL ;
    PORT
      LAYER M4 ;
        RECT  14.982 43.2 15.066 43.224 ;
    END
  END q[138]
  PIN q[139]
    DIRECTION OUTPUT ;
    USE SIGNAL ;
    PORT
      LAYER M4 ;
        RECT  14.982 43.488 15.066 43.512 ;
    END
  END q[139]
  PIN q[13]
    DIRECTION OUTPUT ;
    USE SIGNAL ;
    PORT
      LAYER M4 ;
        RECT  14.982 8.928 15.066 8.952 ;
    END
  END q[13]
  PIN q[140]
    DIRECTION OUTPUT ;
    USE SIGNAL ;
    PORT
      LAYER M4 ;
        RECT  14.982 43.776 15.066 43.8 ;
    END
  END q[140]
  PIN q[141]
    DIRECTION OUTPUT ;
    USE SIGNAL ;
    PORT
      LAYER M4 ;
        RECT  14.982 44.016 15.066 44.04 ;
    END
  END q[141]
  PIN q[142]
    DIRECTION OUTPUT ;
    USE SIGNAL ;
    PORT
      LAYER M4 ;
        RECT  14.982 44.304 15.066 44.328 ;
    END
  END q[142]
  PIN q[143]
    DIRECTION OUTPUT ;
    USE SIGNAL ;
    PORT
      LAYER M4 ;
        RECT  14.982 44.592 15.066 44.616 ;
    END
  END q[143]
  PIN q[144]
    DIRECTION OUTPUT ;
    USE SIGNAL ;
    PORT
      LAYER M4 ;
        RECT  14.982 44.88 15.066 44.904 ;
    END
  END q[144]
  PIN q[145]
    DIRECTION OUTPUT ;
    USE SIGNAL ;
    PORT
      LAYER M4 ;
        RECT  14.982 45.12 15.066 45.144 ;
    END
  END q[145]
  PIN q[146]
    DIRECTION OUTPUT ;
    USE SIGNAL ;
    PORT
      LAYER M4 ;
        RECT  14.982 45.408 15.066 45.432 ;
    END
  END q[146]
  PIN q[147]
    DIRECTION OUTPUT ;
    USE SIGNAL ;
    PORT
      LAYER M4 ;
        RECT  14.982 45.696 15.066 45.72 ;
    END
  END q[147]
  PIN q[148]
    DIRECTION OUTPUT ;
    USE SIGNAL ;
    PORT
      LAYER M4 ;
        RECT  14.982 45.936 15.066 45.96 ;
    END
  END q[148]
  PIN q[149]
    DIRECTION OUTPUT ;
    USE SIGNAL ;
    PORT
      LAYER M4 ;
        RECT  14.982 46.224 15.066 46.248 ;
    END
  END q[149]
  PIN q[14]
    DIRECTION OUTPUT ;
    USE SIGNAL ;
    PORT
      LAYER M4 ;
        RECT  14.982 9.216 15.066 9.24 ;
    END
  END q[14]
  PIN q[150]
    DIRECTION OUTPUT ;
    USE SIGNAL ;
    PORT
      LAYER M4 ;
        RECT  14.982 46.512 15.066 46.536 ;
    END
  END q[150]
  PIN q[151]
    DIRECTION OUTPUT ;
    USE SIGNAL ;
    PORT
      LAYER M4 ;
        RECT  14.982 46.8 15.066 46.824 ;
    END
  END q[151]
  PIN q[152]
    DIRECTION OUTPUT ;
    USE SIGNAL ;
    PORT
      LAYER M4 ;
        RECT  14.982 47.04 15.066 47.064 ;
    END
  END q[152]
  PIN q[153]
    DIRECTION OUTPUT ;
    USE SIGNAL ;
    PORT
      LAYER M4 ;
        RECT  14.982 47.328 15.066 47.352 ;
    END
  END q[153]
  PIN q[154]
    DIRECTION OUTPUT ;
    USE SIGNAL ;
    PORT
      LAYER M4 ;
        RECT  14.982 47.616 15.066 47.64 ;
    END
  END q[154]
  PIN q[155]
    DIRECTION OUTPUT ;
    USE SIGNAL ;
    PORT
      LAYER M4 ;
        RECT  14.982 47.856 15.066 47.88 ;
    END
  END q[155]
  PIN q[156]
    DIRECTION OUTPUT ;
    USE SIGNAL ;
    PORT
      LAYER M4 ;
        RECT  14.982 48.144 15.066 48.168 ;
    END
  END q[156]
  PIN q[157]
    DIRECTION OUTPUT ;
    USE SIGNAL ;
    PORT
      LAYER M4 ;
        RECT  14.982 48.432 15.066 48.456 ;
    END
  END q[157]
  PIN q[158]
    DIRECTION OUTPUT ;
    USE SIGNAL ;
    PORT
      LAYER M4 ;
        RECT  14.982 48.72 15.066 48.744 ;
    END
  END q[158]
  PIN q[159]
    DIRECTION OUTPUT ;
    USE SIGNAL ;
    PORT
      LAYER M4 ;
        RECT  14.982 48.96 15.066 48.984 ;
    END
  END q[159]
  PIN q[15]
    DIRECTION OUTPUT ;
    USE SIGNAL ;
    PORT
      LAYER M4 ;
        RECT  14.982 9.504 15.066 9.528 ;
    END
  END q[15]
  PIN q[160]
    DIRECTION OUTPUT ;
    USE SIGNAL ;
    PORT
      LAYER M4 ;
        RECT  14.982 49.248 15.066 49.272 ;
    END
  END q[160]
  PIN q[161]
    DIRECTION OUTPUT ;
    USE SIGNAL ;
    PORT
      LAYER M4 ;
        RECT  14.982 49.536 15.066 49.56 ;
    END
  END q[161]
  PIN q[162]
    DIRECTION OUTPUT ;
    USE SIGNAL ;
    PORT
      LAYER M4 ;
        RECT  14.982 49.776 15.066 49.8 ;
    END
  END q[162]
  PIN q[163]
    DIRECTION OUTPUT ;
    USE SIGNAL ;
    PORT
      LAYER M4 ;
        RECT  14.982 50.064 15.066 50.088 ;
    END
  END q[163]
  PIN q[164]
    DIRECTION OUTPUT ;
    USE SIGNAL ;
    PORT
      LAYER M4 ;
        RECT  14.982 50.352 15.066 50.376 ;
    END
  END q[164]
  PIN q[165]
    DIRECTION OUTPUT ;
    USE SIGNAL ;
    PORT
      LAYER M4 ;
        RECT  14.982 50.64 15.066 50.664 ;
    END
  END q[165]
  PIN q[166]
    DIRECTION OUTPUT ;
    USE SIGNAL ;
    PORT
      LAYER M4 ;
        RECT  14.982 50.88 15.066 50.904 ;
    END
  END q[166]
  PIN q[167]
    DIRECTION OUTPUT ;
    USE SIGNAL ;
    PORT
      LAYER M4 ;
        RECT  14.982 51.168 15.066 51.192 ;
    END
  END q[167]
  PIN q[168]
    DIRECTION OUTPUT ;
    USE SIGNAL ;
    PORT
      LAYER M4 ;
        RECT  14.982 51.456 15.066 51.48 ;
    END
  END q[168]
  PIN q[169]
    DIRECTION OUTPUT ;
    USE SIGNAL ;
    PORT
      LAYER M4 ;
        RECT  14.982 51.696 15.066 51.72 ;
    END
  END q[169]
  PIN q[16]
    DIRECTION OUTPUT ;
    USE SIGNAL ;
    PORT
      LAYER M4 ;
        RECT  14.982 9.792 15.066 9.816 ;
    END
  END q[16]
  PIN q[170]
    DIRECTION OUTPUT ;
    USE SIGNAL ;
    PORT
      LAYER M4 ;
        RECT  14.982 51.984 15.066 52.008 ;
    END
  END q[170]
  PIN q[171]
    DIRECTION OUTPUT ;
    USE SIGNAL ;
    PORT
      LAYER M4 ;
        RECT  14.982 52.272 15.066 52.296 ;
    END
  END q[171]
  PIN q[172]
    DIRECTION OUTPUT ;
    USE SIGNAL ;
    PORT
      LAYER M4 ;
        RECT  14.982 52.512 15.066 52.536 ;
    END
  END q[172]
  PIN q[173]
    DIRECTION OUTPUT ;
    USE SIGNAL ;
    PORT
      LAYER M4 ;
        RECT  14.982 52.8 15.066 52.824 ;
    END
  END q[173]
  PIN q[174]
    DIRECTION OUTPUT ;
    USE SIGNAL ;
    PORT
      LAYER M4 ;
        RECT  14.982 53.088 15.066 53.112 ;
    END
  END q[174]
  PIN q[175]
    DIRECTION OUTPUT ;
    USE SIGNAL ;
    PORT
      LAYER M4 ;
        RECT  14.982 53.376 15.066 53.4 ;
    END
  END q[175]
  PIN q[176]
    DIRECTION OUTPUT ;
    USE SIGNAL ;
    PORT
      LAYER M4 ;
        RECT  14.982 53.616 15.066 53.64 ;
    END
  END q[176]
  PIN q[177]
    DIRECTION OUTPUT ;
    USE SIGNAL ;
    PORT
      LAYER M4 ;
        RECT  14.982 53.904 15.066 53.928 ;
    END
  END q[177]
  PIN q[178]
    DIRECTION OUTPUT ;
    USE SIGNAL ;
    PORT
      LAYER M4 ;
        RECT  14.982 54.192 15.066 54.216 ;
    END
  END q[178]
  PIN q[179]
    DIRECTION OUTPUT ;
    USE SIGNAL ;
    PORT
      LAYER M4 ;
        RECT  14.982 54.432 15.066 54.456 ;
    END
  END q[179]
  PIN q[17]
    DIRECTION OUTPUT ;
    USE SIGNAL ;
    PORT
      LAYER M4 ;
        RECT  14.982 10.032 15.066 10.056 ;
    END
  END q[17]
  PIN q[180]
    DIRECTION OUTPUT ;
    USE SIGNAL ;
    PORT
      LAYER M4 ;
        RECT  14.982 54.72 15.066 54.744 ;
    END
  END q[180]
  PIN q[181]
    DIRECTION OUTPUT ;
    USE SIGNAL ;
    PORT
      LAYER M4 ;
        RECT  14.982 55.008 15.066 55.032 ;
    END
  END q[181]
  PIN q[182]
    DIRECTION OUTPUT ;
    USE SIGNAL ;
    PORT
      LAYER M4 ;
        RECT  14.982 55.296 15.066 55.32 ;
    END
  END q[182]
  PIN q[183]
    DIRECTION OUTPUT ;
    USE SIGNAL ;
    PORT
      LAYER M4 ;
        RECT  14.982 55.536 15.066 55.56 ;
    END
  END q[183]
  PIN q[184]
    DIRECTION OUTPUT ;
    USE SIGNAL ;
    PORT
      LAYER M4 ;
        RECT  14.982 55.824 15.066 55.848 ;
    END
  END q[184]
  PIN q[185]
    DIRECTION OUTPUT ;
    USE SIGNAL ;
    PORT
      LAYER M4 ;
        RECT  14.982 56.112 15.066 56.136 ;
    END
  END q[185]
  PIN q[186]
    DIRECTION OUTPUT ;
    USE SIGNAL ;
    PORT
      LAYER M4 ;
        RECT  14.982 56.352 15.066 56.376 ;
    END
  END q[186]
  PIN q[187]
    DIRECTION OUTPUT ;
    USE SIGNAL ;
    PORT
      LAYER M4 ;
        RECT  14.982 56.64 15.066 56.664 ;
    END
  END q[187]
  PIN q[188]
    DIRECTION OUTPUT ;
    USE SIGNAL ;
    PORT
      LAYER M4 ;
        RECT  14.982 56.928 15.066 56.952 ;
    END
  END q[188]
  PIN q[189]
    DIRECTION OUTPUT ;
    USE SIGNAL ;
    PORT
      LAYER M4 ;
        RECT  14.982 57.216 15.066 57.24 ;
    END
  END q[189]
  PIN q[18]
    DIRECTION OUTPUT ;
    USE SIGNAL ;
    PORT
      LAYER M4 ;
        RECT  14.982 10.32 15.066 10.344 ;
    END
  END q[18]
  PIN q[190]
    DIRECTION OUTPUT ;
    USE SIGNAL ;
    PORT
      LAYER M4 ;
        RECT  14.982 57.456 15.066 57.48 ;
    END
  END q[190]
  PIN q[191]
    DIRECTION OUTPUT ;
    USE SIGNAL ;
    PORT
      LAYER M4 ;
        RECT  14.982 57.744 15.066 57.768 ;
    END
  END q[191]
  PIN q[192]
    DIRECTION OUTPUT ;
    USE SIGNAL ;
    PORT
      LAYER M4 ;
        RECT  14.982 58.032 15.066 58.056 ;
    END
  END q[192]
  PIN q[193]
    DIRECTION OUTPUT ;
    USE SIGNAL ;
    PORT
      LAYER M4 ;
        RECT  14.982 58.272 15.066 58.296 ;
    END
  END q[193]
  PIN q[194]
    DIRECTION OUTPUT ;
    USE SIGNAL ;
    PORT
      LAYER M4 ;
        RECT  14.982 58.56 15.066 58.584 ;
    END
  END q[194]
  PIN q[195]
    DIRECTION OUTPUT ;
    USE SIGNAL ;
    PORT
      LAYER M4 ;
        RECT  14.982 58.848 15.066 58.872 ;
    END
  END q[195]
  PIN q[196]
    DIRECTION OUTPUT ;
    USE SIGNAL ;
    PORT
      LAYER M4 ;
        RECT  14.982 59.136 15.066 59.16 ;
    END
  END q[196]
  PIN q[197]
    DIRECTION OUTPUT ;
    USE SIGNAL ;
    PORT
      LAYER M4 ;
        RECT  14.982 59.376 15.066 59.4 ;
    END
  END q[197]
  PIN q[19]
    DIRECTION OUTPUT ;
    USE SIGNAL ;
    PORT
      LAYER M4 ;
        RECT  14.982 10.608 15.066 10.632 ;
    END
  END q[19]
  PIN q[1]
    DIRECTION OUTPUT ;
    USE SIGNAL ;
    PORT
      LAYER M4 ;
        RECT  14.982 5.664 15.066 5.688 ;
    END
  END q[1]
  PIN q[20]
    DIRECTION OUTPUT ;
    USE SIGNAL ;
    PORT
      LAYER M4 ;
        RECT  14.982 10.848 15.066 10.872 ;
    END
  END q[20]
  PIN q[21]
    DIRECTION OUTPUT ;
    USE SIGNAL ;
    PORT
      LAYER M4 ;
        RECT  14.982 11.136 15.066 11.16 ;
    END
  END q[21]
  PIN q[22]
    DIRECTION OUTPUT ;
    USE SIGNAL ;
    PORT
      LAYER M4 ;
        RECT  14.982 11.424 15.066 11.448 ;
    END
  END q[22]
  PIN q[23]
    DIRECTION OUTPUT ;
    USE SIGNAL ;
    PORT
      LAYER M4 ;
        RECT  14.982 11.712 15.066 11.736 ;
    END
  END q[23]
  PIN q[24]
    DIRECTION OUTPUT ;
    USE SIGNAL ;
    PORT
      LAYER M4 ;
        RECT  14.982 11.952 15.066 11.976 ;
    END
  END q[24]
  PIN q[25]
    DIRECTION OUTPUT ;
    USE SIGNAL ;
    PORT
      LAYER M4 ;
        RECT  14.982 12.24 15.066 12.264 ;
    END
  END q[25]
  PIN q[26]
    DIRECTION OUTPUT ;
    USE SIGNAL ;
    PORT
      LAYER M4 ;
        RECT  14.982 12.528 15.066 12.552 ;
    END
  END q[26]
  PIN q[27]
    DIRECTION OUTPUT ;
    USE SIGNAL ;
    PORT
      LAYER M4 ;
        RECT  14.982 12.768 15.066 12.792 ;
    END
  END q[27]
  PIN q[28]
    DIRECTION OUTPUT ;
    USE SIGNAL ;
    PORT
      LAYER M4 ;
        RECT  14.982 13.056 15.066 13.08 ;
    END
  END q[28]
  PIN q[29]
    DIRECTION OUTPUT ;
    USE SIGNAL ;
    PORT
      LAYER M4 ;
        RECT  14.982 13.344 15.066 13.368 ;
    END
  END q[29]
  PIN q[2]
    DIRECTION OUTPUT ;
    USE SIGNAL ;
    PORT
      LAYER M4 ;
        RECT  14.982 5.952 15.066 5.976 ;
    END
  END q[2]
  PIN q[30]
    DIRECTION OUTPUT ;
    USE SIGNAL ;
    PORT
      LAYER M4 ;
        RECT  14.982 13.632 15.066 13.656 ;
    END
  END q[30]
  PIN q[31]
    DIRECTION OUTPUT ;
    USE SIGNAL ;
    PORT
      LAYER M4 ;
        RECT  14.982 13.872 15.066 13.896 ;
    END
  END q[31]
  PIN q[32]
    DIRECTION OUTPUT ;
    USE SIGNAL ;
    PORT
      LAYER M4 ;
        RECT  14.982 14.16 15.066 14.184 ;
    END
  END q[32]
  PIN q[33]
    DIRECTION OUTPUT ;
    USE SIGNAL ;
    PORT
      LAYER M4 ;
        RECT  14.982 14.448 15.066 14.472 ;
    END
  END q[33]
  PIN q[34]
    DIRECTION OUTPUT ;
    USE SIGNAL ;
    PORT
      LAYER M4 ;
        RECT  14.982 14.688 15.066 14.712 ;
    END
  END q[34]
  PIN q[35]
    DIRECTION OUTPUT ;
    USE SIGNAL ;
    PORT
      LAYER M4 ;
        RECT  14.982 14.976 15.066 15 ;
    END
  END q[35]
  PIN q[36]
    DIRECTION OUTPUT ;
    USE SIGNAL ;
    PORT
      LAYER M4 ;
        RECT  14.982 15.264 15.066 15.288 ;
    END
  END q[36]
  PIN q[37]
    DIRECTION OUTPUT ;
    USE SIGNAL ;
    PORT
      LAYER M4 ;
        RECT  14.982 15.552 15.066 15.576 ;
    END
  END q[37]
  PIN q[38]
    DIRECTION OUTPUT ;
    USE SIGNAL ;
    PORT
      LAYER M4 ;
        RECT  14.982 15.792 15.066 15.816 ;
    END
  END q[38]
  PIN q[39]
    DIRECTION OUTPUT ;
    USE SIGNAL ;
    PORT
      LAYER M4 ;
        RECT  14.982 16.08 15.066 16.104 ;
    END
  END q[39]
  PIN q[3]
    DIRECTION OUTPUT ;
    USE SIGNAL ;
    PORT
      LAYER M4 ;
        RECT  14.982 6.192 15.066 6.216 ;
    END
  END q[3]
  PIN q[40]
    DIRECTION OUTPUT ;
    USE SIGNAL ;
    PORT
      LAYER M4 ;
        RECT  14.982 16.368 15.066 16.392 ;
    END
  END q[40]
  PIN q[41]
    DIRECTION OUTPUT ;
    USE SIGNAL ;
    PORT
      LAYER M4 ;
        RECT  14.982 16.608 15.066 16.632 ;
    END
  END q[41]
  PIN q[42]
    DIRECTION OUTPUT ;
    USE SIGNAL ;
    PORT
      LAYER M4 ;
        RECT  14.982 16.896 15.066 16.92 ;
    END
  END q[42]
  PIN q[43]
    DIRECTION OUTPUT ;
    USE SIGNAL ;
    PORT
      LAYER M4 ;
        RECT  14.982 17.184 15.066 17.208 ;
    END
  END q[43]
  PIN q[44]
    DIRECTION OUTPUT ;
    USE SIGNAL ;
    PORT
      LAYER M4 ;
        RECT  14.982 17.472 15.066 17.496 ;
    END
  END q[44]
  PIN q[45]
    DIRECTION OUTPUT ;
    USE SIGNAL ;
    PORT
      LAYER M4 ;
        RECT  14.982 17.712 15.066 17.736 ;
    END
  END q[45]
  PIN q[46]
    DIRECTION OUTPUT ;
    USE SIGNAL ;
    PORT
      LAYER M4 ;
        RECT  14.982 18 15.066 18.024 ;
    END
  END q[46]
  PIN q[47]
    DIRECTION OUTPUT ;
    USE SIGNAL ;
    PORT
      LAYER M4 ;
        RECT  14.982 18.288 15.066 18.312 ;
    END
  END q[47]
  PIN q[48]
    DIRECTION OUTPUT ;
    USE SIGNAL ;
    PORT
      LAYER M4 ;
        RECT  14.982 18.528 15.066 18.552 ;
    END
  END q[48]
  PIN q[49]
    DIRECTION OUTPUT ;
    USE SIGNAL ;
    PORT
      LAYER M4 ;
        RECT  14.982 18.816 15.066 18.84 ;
    END
  END q[49]
  PIN q[4]
    DIRECTION OUTPUT ;
    USE SIGNAL ;
    PORT
      LAYER M4 ;
        RECT  14.982 6.48 15.066 6.504 ;
    END
  END q[4]
  PIN q[50]
    DIRECTION OUTPUT ;
    USE SIGNAL ;
    PORT
      LAYER M4 ;
        RECT  14.982 19.104 15.066 19.128 ;
    END
  END q[50]
  PIN q[51]
    DIRECTION OUTPUT ;
    USE SIGNAL ;
    PORT
      LAYER M4 ;
        RECT  14.982 19.344 15.066 19.368 ;
    END
  END q[51]
  PIN q[52]
    DIRECTION OUTPUT ;
    USE SIGNAL ;
    PORT
      LAYER M4 ;
        RECT  14.982 19.632 15.066 19.656 ;
    END
  END q[52]
  PIN q[53]
    DIRECTION OUTPUT ;
    USE SIGNAL ;
    PORT
      LAYER M4 ;
        RECT  14.982 19.92 15.066 19.944 ;
    END
  END q[53]
  PIN q[54]
    DIRECTION OUTPUT ;
    USE SIGNAL ;
    PORT
      LAYER M4 ;
        RECT  14.982 20.208 15.066 20.232 ;
    END
  END q[54]
  PIN q[55]
    DIRECTION OUTPUT ;
    USE SIGNAL ;
    PORT
      LAYER M4 ;
        RECT  14.982 20.448 15.066 20.472 ;
    END
  END q[55]
  PIN q[56]
    DIRECTION OUTPUT ;
    USE SIGNAL ;
    PORT
      LAYER M4 ;
        RECT  14.982 20.736 15.066 20.76 ;
    END
  END q[56]
  PIN q[57]
    DIRECTION OUTPUT ;
    USE SIGNAL ;
    PORT
      LAYER M4 ;
        RECT  14.982 21.024 15.066 21.048 ;
    END
  END q[57]
  PIN q[58]
    DIRECTION OUTPUT ;
    USE SIGNAL ;
    PORT
      LAYER M4 ;
        RECT  14.982 21.264 15.066 21.288 ;
    END
  END q[58]
  PIN q[59]
    DIRECTION OUTPUT ;
    USE SIGNAL ;
    PORT
      LAYER M4 ;
        RECT  14.982 21.552 15.066 21.576 ;
    END
  END q[59]
  PIN q[5]
    DIRECTION OUTPUT ;
    USE SIGNAL ;
    PORT
      LAYER M4 ;
        RECT  14.982 6.768 15.066 6.792 ;
    END
  END q[5]
  PIN q[60]
    DIRECTION OUTPUT ;
    USE SIGNAL ;
    PORT
      LAYER M4 ;
        RECT  14.982 21.84 15.066 21.864 ;
    END
  END q[60]
  PIN q[61]
    DIRECTION OUTPUT ;
    USE SIGNAL ;
    PORT
      LAYER M4 ;
        RECT  14.982 22.128 15.066 22.152 ;
    END
  END q[61]
  PIN q[62]
    DIRECTION OUTPUT ;
    USE SIGNAL ;
    PORT
      LAYER M4 ;
        RECT  14.982 22.368 15.066 22.392 ;
    END
  END q[62]
  PIN q[63]
    DIRECTION OUTPUT ;
    USE SIGNAL ;
    PORT
      LAYER M4 ;
        RECT  14.982 22.656 15.066 22.68 ;
    END
  END q[63]
  PIN q[64]
    DIRECTION OUTPUT ;
    USE SIGNAL ;
    PORT
      LAYER M4 ;
        RECT  14.982 22.944 15.066 22.968 ;
    END
  END q[64]
  PIN q[65]
    DIRECTION OUTPUT ;
    USE SIGNAL ;
    PORT
      LAYER M4 ;
        RECT  14.982 23.184 15.066 23.208 ;
    END
  END q[65]
  PIN q[66]
    DIRECTION OUTPUT ;
    USE SIGNAL ;
    PORT
      LAYER M4 ;
        RECT  14.982 23.472 15.066 23.496 ;
    END
  END q[66]
  PIN q[67]
    DIRECTION OUTPUT ;
    USE SIGNAL ;
    PORT
      LAYER M4 ;
        RECT  14.982 23.76 15.066 23.784 ;
    END
  END q[67]
  PIN q[68]
    DIRECTION OUTPUT ;
    USE SIGNAL ;
    PORT
      LAYER M4 ;
        RECT  14.982 24.048 15.066 24.072 ;
    END
  END q[68]
  PIN q[69]
    DIRECTION OUTPUT ;
    USE SIGNAL ;
    PORT
      LAYER M4 ;
        RECT  14.982 24.288 15.066 24.312 ;
    END
  END q[69]
  PIN q[6]
    DIRECTION OUTPUT ;
    USE SIGNAL ;
    PORT
      LAYER M4 ;
        RECT  14.982 7.056 15.066 7.08 ;
    END
  END q[6]
  PIN q[70]
    DIRECTION OUTPUT ;
    USE SIGNAL ;
    PORT
      LAYER M4 ;
        RECT  14.982 24.576 15.066 24.6 ;
    END
  END q[70]
  PIN q[71]
    DIRECTION OUTPUT ;
    USE SIGNAL ;
    PORT
      LAYER M4 ;
        RECT  14.982 24.864 15.066 24.888 ;
    END
  END q[71]
  PIN q[72]
    DIRECTION OUTPUT ;
    USE SIGNAL ;
    PORT
      LAYER M4 ;
        RECT  14.982 25.104 15.066 25.128 ;
    END
  END q[72]
  PIN q[73]
    DIRECTION OUTPUT ;
    USE SIGNAL ;
    PORT
      LAYER M4 ;
        RECT  14.982 25.392 15.066 25.416 ;
    END
  END q[73]
  PIN q[74]
    DIRECTION OUTPUT ;
    USE SIGNAL ;
    PORT
      LAYER M4 ;
        RECT  14.982 25.68 15.066 25.704 ;
    END
  END q[74]
  PIN q[75]
    DIRECTION OUTPUT ;
    USE SIGNAL ;
    PORT
      LAYER M4 ;
        RECT  14.982 25.968 15.066 25.992 ;
    END
  END q[75]
  PIN q[76]
    DIRECTION OUTPUT ;
    USE SIGNAL ;
    PORT
      LAYER M4 ;
        RECT  14.982 26.208 15.066 26.232 ;
    END
  END q[76]
  PIN q[77]
    DIRECTION OUTPUT ;
    USE SIGNAL ;
    PORT
      LAYER M4 ;
        RECT  14.982 26.496 15.066 26.52 ;
    END
  END q[77]
  PIN q[78]
    DIRECTION OUTPUT ;
    USE SIGNAL ;
    PORT
      LAYER M4 ;
        RECT  14.982 26.784 15.066 26.808 ;
    END
  END q[78]
  PIN q[79]
    DIRECTION OUTPUT ;
    USE SIGNAL ;
    PORT
      LAYER M4 ;
        RECT  14.982 27.024 15.066 27.048 ;
    END
  END q[79]
  PIN q[7]
    DIRECTION OUTPUT ;
    USE SIGNAL ;
    PORT
      LAYER M4 ;
        RECT  14.982 7.296 15.066 7.32 ;
    END
  END q[7]
  PIN q[80]
    DIRECTION OUTPUT ;
    USE SIGNAL ;
    PORT
      LAYER M4 ;
        RECT  14.982 27.312 15.066 27.336 ;
    END
  END q[80]
  PIN q[81]
    DIRECTION OUTPUT ;
    USE SIGNAL ;
    PORT
      LAYER M4 ;
        RECT  14.982 27.6 15.066 27.624 ;
    END
  END q[81]
  PIN q[82]
    DIRECTION OUTPUT ;
    USE SIGNAL ;
    PORT
      LAYER M4 ;
        RECT  14.982 27.888 15.066 27.912 ;
    END
  END q[82]
  PIN q[83]
    DIRECTION OUTPUT ;
    USE SIGNAL ;
    PORT
      LAYER M4 ;
        RECT  14.982 28.128 15.066 28.152 ;
    END
  END q[83]
  PIN q[84]
    DIRECTION OUTPUT ;
    USE SIGNAL ;
    PORT
      LAYER M4 ;
        RECT  14.982 28.416 15.066 28.44 ;
    END
  END q[84]
  PIN q[85]
    DIRECTION OUTPUT ;
    USE SIGNAL ;
    PORT
      LAYER M4 ;
        RECT  14.982 28.704 15.066 28.728 ;
    END
  END q[85]
  PIN q[86]
    DIRECTION OUTPUT ;
    USE SIGNAL ;
    PORT
      LAYER M4 ;
        RECT  14.982 28.944 15.066 28.968 ;
    END
  END q[86]
  PIN q[87]
    DIRECTION OUTPUT ;
    USE SIGNAL ;
    PORT
      LAYER M4 ;
        RECT  14.982 29.232 15.066 29.256 ;
    END
  END q[87]
  PIN q[88]
    DIRECTION OUTPUT ;
    USE SIGNAL ;
    PORT
      LAYER M4 ;
        RECT  14.982 29.52 15.066 29.544 ;
    END
  END q[88]
  PIN q[89]
    DIRECTION OUTPUT ;
    USE SIGNAL ;
    PORT
      LAYER M4 ;
        RECT  14.982 29.76 15.066 29.784 ;
    END
  END q[89]
  PIN q[8]
    DIRECTION OUTPUT ;
    USE SIGNAL ;
    PORT
      LAYER M4 ;
        RECT  14.982 7.584 15.066 7.608 ;
    END
  END q[8]
  PIN q[90]
    DIRECTION OUTPUT ;
    USE SIGNAL ;
    PORT
      LAYER M4 ;
        RECT  14.982 30.048 15.066 30.072 ;
    END
  END q[90]
  PIN q[91]
    DIRECTION OUTPUT ;
    USE SIGNAL ;
    PORT
      LAYER M4 ;
        RECT  14.982 30.336 15.066 30.36 ;
    END
  END q[91]
  PIN q[92]
    DIRECTION OUTPUT ;
    USE SIGNAL ;
    PORT
      LAYER M4 ;
        RECT  14.982 30.624 15.066 30.648 ;
    END
  END q[92]
  PIN q[93]
    DIRECTION OUTPUT ;
    USE SIGNAL ;
    PORT
      LAYER M4 ;
        RECT  14.982 30.864 15.066 30.888 ;
    END
  END q[93]
  PIN q[94]
    DIRECTION OUTPUT ;
    USE SIGNAL ;
    PORT
      LAYER M4 ;
        RECT  14.982 31.152 15.066 31.176 ;
    END
  END q[94]
  PIN q[95]
    DIRECTION OUTPUT ;
    USE SIGNAL ;
    PORT
      LAYER M4 ;
        RECT  14.982 31.44 15.066 31.464 ;
    END
  END q[95]
  PIN q[96]
    DIRECTION OUTPUT ;
    USE SIGNAL ;
    PORT
      LAYER M4 ;
        RECT  14.982 31.68 15.066 31.704 ;
    END
  END q[96]
  PIN q[97]
    DIRECTION OUTPUT ;
    USE SIGNAL ;
    PORT
      LAYER M4 ;
        RECT  14.982 31.968 15.066 31.992 ;
    END
  END q[97]
  PIN q[98]
    DIRECTION OUTPUT ;
    USE SIGNAL ;
    PORT
      LAYER M4 ;
        RECT  14.982 32.256 15.066 32.28 ;
    END
  END q[98]
  PIN q[99]
    DIRECTION OUTPUT ;
    USE SIGNAL ;
    PORT
      LAYER M4 ;
        RECT  14.982 32.544 15.066 32.568 ;
    END
  END q[99]
  PIN q[9]
    DIRECTION OUTPUT ;
    USE SIGNAL ;
    PORT
      LAYER M4 ;
        RECT  14.982 7.872 15.066 7.896 ;
    END
  END q[9]
  PIN rst_n
    DIRECTION INPUT ;
    USE SIGNAL ;
    PORT
      LAYER M5 ;
        RECT  9.696 0.054 9.72 0.138 ;
    END
    PORT
      LAYER M5 ;
        RECT  9.696 0.08 9.72 0.563 ;
    END
  END rst_n
  PIN VDD
    DIRECTION INOUT ;
    USE POWER ;
    PORT
      LAYER M5 ;
        RECT  10.692 2.151 10.812 62.649 ;
        RECT  7.992 2.151 8.112 62.649 ;
        RECT  5.292 2.151 5.412 62.649 ;
        RECT  2.592 2.151 2.712 62.649 ;
    END
  END VDD
  PIN VSS
    DIRECTION INOUT ;
    USE GROUND ;
    PORT
      LAYER M5 ;
        RECT  10.5 2.137 10.62 62.663 ;
        RECT  7.8 2.137 7.92 62.663 ;
        RECT  5.1 2.137 5.22 62.663 ;
        RECT  2.4 2.137 2.52 62.663 ;
    END
  END VSS
  # OT_OBS_CLOSED layer=M5 d_um=1.536 added=21
  OBS
    LAYER RVTN ;
     RECT  2.16 2.16 12.96 2.295 ;
     RECT  2.16 2.565 12.96 2.835 ;
     RECT  2.16 3.105 12.96 3.375 ;
     RECT  2.16 3.645 12.96 3.915 ;
     RECT  2.16 4.185 12.96 4.455 ;
     RECT  2.16 4.725 12.96 4.995 ;
     RECT  2.16 5.265 12.96 5.535 ;
     RECT  2.16 5.805 12.96 6.075 ;
     RECT  2.16 6.345 12.96 6.615 ;
     RECT  2.16 6.885 12.96 7.155 ;
     RECT  2.16 7.425 12.96 7.695 ;
     RECT  2.16 7.965 12.96 8.235 ;
     RECT  2.16 8.505 12.96 8.775 ;
     RECT  2.16 9.045 12.96 9.315 ;
     RECT  2.16 9.585 12.96 9.855 ;
     RECT  2.16 10.125 12.96 10.395 ;
     RECT  2.16 10.665 12.96 10.935 ;
     RECT  2.16 11.205 12.96 11.475 ;
     RECT  2.16 11.745 12.96 12.015 ;
     RECT  2.16 12.285 12.96 12.555 ;
     RECT  2.16 12.825 12.96 13.095 ;
     RECT  2.16 13.365 12.96 13.635 ;
     RECT  2.16 13.905 12.96 14.175 ;
     RECT  2.16 14.445 12.96 14.715 ;
     RECT  2.16 14.985 12.96 15.255 ;
     RECT  2.16 15.525 12.96 15.795 ;
     RECT  2.16 16.065 12.96 16.335 ;
     RECT  2.16 16.605 12.96 16.875 ;
     RECT  2.16 17.145 12.96 17.415 ;
     RECT  2.16 17.685 12.96 17.955 ;
     RECT  2.16 18.225 12.96 18.495 ;
     RECT  2.16 18.765 12.96 19.035 ;
     RECT  2.16 19.305 12.96 19.575 ;
     RECT  2.16 19.845 12.96 20.115 ;
     RECT  2.16 20.385 12.96 20.655 ;
     RECT  2.16 20.925 12.96 21.195 ;
     RECT  2.16 21.465 12.96 21.735 ;
     RECT  2.16 22.005 12.96 22.275 ;
     RECT  2.16 22.545 12.96 22.815 ;
     RECT  2.16 23.085 12.96 23.355 ;
     RECT  2.16 23.625 12.96 23.895 ;
     RECT  2.16 24.165 12.96 24.435 ;
     RECT  2.16 24.705 12.96 24.975 ;
     RECT  2.16 25.245 12.96 25.515 ;
     RECT  2.16 25.785 12.96 26.055 ;
     RECT  2.16 26.325 12.96 26.595 ;
     RECT  2.16 26.865 12.96 27.135 ;
     RECT  2.16 27.405 12.96 27.675 ;
     RECT  2.16 27.945 12.96 28.215 ;
     RECT  2.16 28.485 12.96 28.755 ;
     RECT  2.16 29.025 12.96 29.295 ;
     RECT  2.16 29.565 12.96 29.835 ;
     RECT  2.16 30.105 12.96 30.375 ;
     RECT  2.16 30.645 12.96 30.915 ;
     RECT  2.16 31.185 12.96 31.455 ;
     RECT  2.16 31.725 12.96 31.995 ;
     RECT  2.16 32.265 12.96 32.535 ;
     RECT  2.16 32.805 12.96 33.075 ;
     RECT  2.16 33.345 12.96 33.615 ;
     RECT  2.16 33.885 12.96 34.155 ;
     RECT  2.16 34.425 12.96 34.695 ;
     RECT  2.16 34.965 12.96 35.235 ;
     RECT  2.16 35.505 12.96 35.775 ;
     RECT  2.16 36.045 12.96 36.315 ;
     RECT  2.16 36.585 12.96 36.855 ;
     RECT  2.16 37.125 12.96 37.395 ;
     RECT  2.16 37.665 12.96 37.935 ;
     RECT  2.16 38.205 12.96 38.475 ;
     RECT  2.16 38.745 12.96 39.015 ;
     RECT  2.16 39.285 12.96 39.555 ;
     RECT  2.16 39.825 12.96 40.095 ;
     RECT  2.16 40.365 12.96 40.635 ;
     RECT  2.16 40.905 12.96 41.175 ;
     RECT  2.16 41.445 12.96 41.715 ;
     RECT  2.16 41.985 12.96 42.255 ;
     RECT  2.16 42.525 12.96 42.795 ;
     RECT  2.16 43.065 12.96 43.335 ;
     RECT  2.16 43.605 12.96 43.875 ;
     RECT  2.16 44.145 12.96 44.415 ;
     RECT  2.16 44.685 12.96 44.955 ;
     RECT  2.16 45.225 12.96 45.495 ;
     RECT  2.16 45.765 12.96 46.035 ;
     RECT  2.16 46.305 12.96 46.575 ;
     RECT  2.16 46.845 12.96 47.115 ;
     RECT  2.16 47.385 12.96 47.655 ;
     RECT  2.16 47.925 12.96 48.195 ;
     RECT  2.16 48.465 12.96 48.735 ;
     RECT  2.16 49.005 12.96 49.275 ;
     RECT  2.16 49.545 12.96 49.815 ;
     RECT  2.16 50.085 12.96 50.355 ;
     RECT  2.16 50.625 12.96 50.895 ;
     RECT  2.16 51.165 12.96 51.435 ;
     RECT  2.16 51.705 12.96 51.975 ;
     RECT  2.16 52.245 12.96 52.515 ;
     RECT  2.16 52.785 12.96 53.055 ;
     RECT  2.16 53.325 12.96 53.595 ;
     RECT  2.16 53.865 12.96 54.135 ;
     RECT  2.16 54.405 12.96 54.675 ;
     RECT  2.16 54.945 12.96 55.215 ;
     RECT  2.16 55.485 12.96 55.755 ;
     RECT  2.16 56.025 12.96 56.295 ;
     RECT  2.16 56.565 12.96 56.835 ;
     RECT  2.16 57.105 12.96 57.375 ;
     RECT  2.16 57.645 12.96 57.915 ;
     RECT  2.16 58.185 12.96 58.455 ;
     RECT  2.16 58.725 12.96 58.995 ;
     RECT  2.16 59.265 12.96 59.535 ;
     RECT  2.16 59.805 12.96 60.075 ;
     RECT  2.16 60.345 12.96 60.615 ;
     RECT  2.16 60.885 12.96 61.155 ;
     RECT  2.16 61.425 12.96 61.695 ;
     RECT  2.16 61.965 12.96 62.235 ;
     RECT  2.16 62.505 12.96 62.64 ;
    LAYER RVTP ;
     RECT  2.16 2.295 12.96 2.565 ;
     RECT  2.16 2.835 12.96 3.105 ;
     RECT  2.16 3.375 12.96 3.645 ;
     RECT  2.16 3.915 12.96 4.185 ;
     RECT  2.16 4.455 12.96 4.725 ;
     RECT  2.16 4.995 12.96 5.265 ;
     RECT  2.16 5.535 12.96 5.805 ;
     RECT  2.16 6.075 12.96 6.345 ;
     RECT  2.16 6.615 12.96 6.885 ;
     RECT  2.16 7.155 12.96 7.425 ;
     RECT  2.16 7.695 12.96 7.965 ;
     RECT  2.16 8.235 12.96 8.505 ;
     RECT  2.16 8.775 12.96 9.045 ;
     RECT  2.16 9.315 12.96 9.585 ;
     RECT  2.16 9.855 12.96 10.125 ;
     RECT  2.16 10.395 12.96 10.665 ;
     RECT  2.16 10.935 12.96 11.205 ;
     RECT  2.16 11.475 12.96 11.745 ;
     RECT  2.16 12.015 12.96 12.285 ;
     RECT  2.16 12.555 12.96 12.825 ;
     RECT  2.16 13.095 12.96 13.365 ;
     RECT  2.16 13.635 12.96 13.905 ;
     RECT  2.16 14.175 12.96 14.445 ;
     RECT  2.16 14.715 12.96 14.985 ;
     RECT  2.16 15.255 12.96 15.525 ;
     RECT  2.16 15.795 12.96 16.065 ;
     RECT  2.16 16.335 12.96 16.605 ;
     RECT  2.16 16.875 12.96 17.145 ;
     RECT  2.16 17.415 12.96 17.685 ;
     RECT  2.16 17.955 12.96 18.225 ;
     RECT  2.16 18.495 12.96 18.765 ;
     RECT  2.16 19.035 12.96 19.305 ;
     RECT  2.16 19.575 12.96 19.845 ;
     RECT  2.16 20.115 12.96 20.385 ;
     RECT  2.16 20.655 12.96 20.925 ;
     RECT  2.16 21.195 12.96 21.465 ;
     RECT  2.16 21.735 12.96 22.005 ;
     RECT  2.16 22.275 12.96 22.545 ;
     RECT  2.16 22.815 12.96 23.085 ;
     RECT  2.16 23.355 12.96 23.625 ;
     RECT  2.16 23.895 12.96 24.165 ;
     RECT  2.16 24.435 12.96 24.705 ;
     RECT  2.16 24.975 12.96 25.245 ;
     RECT  2.16 25.515 12.96 25.785 ;
     RECT  2.16 26.055 12.96 26.325 ;
     RECT  2.16 26.595 12.96 26.865 ;
     RECT  2.16 27.135 12.96 27.405 ;
     RECT  2.16 27.675 12.96 27.945 ;
     RECT  2.16 28.215 12.96 28.485 ;
     RECT  2.16 28.755 12.96 29.025 ;
     RECT  2.16 29.295 12.96 29.565 ;
     RECT  2.16 29.835 12.96 30.105 ;
     RECT  2.16 30.375 12.96 30.645 ;
     RECT  2.16 30.915 12.96 31.185 ;
     RECT  2.16 31.455 12.96 31.725 ;
     RECT  2.16 31.995 12.96 32.265 ;
     RECT  2.16 32.535 12.96 32.805 ;
     RECT  2.16 33.075 12.96 33.345 ;
     RECT  2.16 33.615 12.96 33.885 ;
     RECT  2.16 34.155 12.96 34.425 ;
     RECT  2.16 34.695 12.96 34.965 ;
     RECT  2.16 35.235 12.96 35.505 ;
     RECT  2.16 35.775 12.96 36.045 ;
     RECT  2.16 36.315 12.96 36.585 ;
     RECT  2.16 36.855 12.96 37.125 ;
     RECT  2.16 37.395 12.96 37.665 ;
     RECT  2.16 37.935 12.96 38.205 ;
     RECT  2.16 38.475 12.96 38.745 ;
     RECT  2.16 39.015 12.96 39.285 ;
     RECT  2.16 39.555 12.96 39.825 ;
     RECT  2.16 40.095 12.96 40.365 ;
     RECT  2.16 40.635 12.96 40.905 ;
     RECT  2.16 41.175 12.96 41.445 ;
     RECT  2.16 41.715 12.96 41.985 ;
     RECT  2.16 42.255 12.96 42.525 ;
     RECT  2.16 42.795 12.96 43.065 ;
     RECT  2.16 43.335 12.96 43.605 ;
     RECT  2.16 43.875 12.96 44.145 ;
     RECT  2.16 44.415 12.96 44.685 ;
     RECT  2.16 44.955 12.96 45.225 ;
     RECT  2.16 45.495 12.96 45.765 ;
     RECT  2.16 46.035 12.96 46.305 ;
     RECT  2.16 46.575 12.96 46.845 ;
     RECT  2.16 47.115 12.96 47.385 ;
     RECT  2.16 47.655 12.96 47.925 ;
     RECT  2.16 48.195 12.96 48.465 ;
     RECT  2.16 48.735 12.96 49.005 ;
     RECT  2.16 49.275 12.96 49.545 ;
     RECT  2.16 49.815 12.96 50.085 ;
     RECT  2.16 50.355 12.96 50.625 ;
     RECT  2.16 50.895 12.96 51.165 ;
     RECT  2.16 51.435 12.96 51.705 ;
     RECT  2.16 51.975 12.96 52.245 ;
     RECT  2.16 52.515 12.96 52.785 ;
     RECT  2.16 53.055 12.96 53.325 ;
     RECT  2.16 53.595 12.96 53.865 ;
     RECT  2.16 54.135 12.96 54.405 ;
     RECT  2.16 54.675 12.96 54.945 ;
     RECT  2.16 55.215 12.96 55.485 ;
     RECT  2.16 55.755 12.96 56.025 ;
     RECT  2.16 56.295 12.96 56.565 ;
     RECT  2.16 56.835 12.96 57.105 ;
     RECT  2.16 57.375 12.96 57.645 ;
     RECT  2.16 57.915 12.96 58.185 ;
     RECT  2.16 58.455 12.96 58.725 ;
     RECT  2.16 58.995 12.96 59.265 ;
     RECT  2.16 59.535 12.96 59.805 ;
     RECT  2.16 60.075 12.96 60.345 ;
     RECT  2.16 60.615 12.96 60.885 ;
     RECT  2.16 61.155 12.96 61.425 ;
     RECT  2.16 61.695 12.96 61.965 ;
     RECT  2.16 62.235 12.96 62.505 ;
    LAYER M1 ;
     RECT  2.16 2.151 12.96 62.649 ;
    LAYER M2 ;
     RECT  0.535 12.492 2.16 12.51 ;
     RECT  0.139 31.23 2.16 31.248 ;
     RECT  0.139 34.74 2.16 34.758 ;
     RECT  0.139 54.45 2.16 54.468 ;
     RECT  2.16 2.151 12.96 62.649 ;
     RECT  12.96 6.786 13.811 59.994 ;
     RECT  13.811 14.616 13.883 32.724 ;
     RECT  12.96 5.076 14.207 5.904 ;
     RECT  13.811 6.786 14.207 13.824 ;
     RECT  13.811 33.588 14.207 59.994 ;
     RECT  14.207 6.786 14.243 10.314 ;
     RECT  14.207 11.106 14.243 13.824 ;
     RECT  13.883 14.616 14.243 31.914 ;
     RECT  13.883 32.706 14.243 32.724 ;
     RECT  14.207 33.588 14.243 45.414 ;
     RECT  14.207 46.206 14.243 47.844 ;
     RECT  14.207 48.636 14.243 51.354 ;
     RECT  14.207 52.686 14.243 58.104 ;
     RECT  14.207 58.896 14.243 58.914 ;
     RECT  14.207 59.706 14.243 59.994 ;
     RECT  14.243 7.866 14.279 8.262 ;
     RECT  14.279 8.244 14.315 8.262 ;
     RECT  14.207 5.076 14.927 5.364 ;
     RECT  14.927 5.076 14.963 5.094 ;
     RECT  14.243 11.376 14.963 11.394 ;
     RECT  14.243 12.456 14.963 12.474 ;
     RECT  14.243 13.536 14.963 13.554 ;
     RECT  14.243 17.766 14.963 17.784 ;
     RECT  14.243 26.766 14.963 26.784 ;
     RECT  14.243 31.896 14.963 31.914 ;
     RECT  14.243 43.848 14.963 43.866 ;
     RECT  14.243 47.286 14.963 47.304 ;
     RECT  14.243 59.976 14.963 59.994 ;
    LAYER M3 ;
     RECT  2.415 2.143 2.505 2.413 ;
     RECT  5.115 2.143 5.205 2.413 ;
     RECT  7.815 2.143 7.905 2.413 ;
     RECT  10.515 2.143 10.605 2.413 ;
     RECT  14.94 5.071 14.958 5.233 ;
     RECT  12.636 5.035 12.654 5.305 ;
     RECT  2.415 2.413 2.697 5.419 ;
     RECT  12.024 5.305 12.654 5.431 ;
     RECT  14.22 5.233 14.958 5.453 ;
     RECT  11.664 5.431 12.654 5.531 ;
     RECT  2.304 5.419 2.697 5.575 ;
     RECT  3.816 5.539 3.834 5.575 ;
     RECT  11.736 5.531 12.654 5.575 ;
     RECT  11.736 5.575 13.122 5.693 ;
     RECT  5.115 2.413 5.397 5.737 ;
     RECT  2.304 5.575 4.194 5.809 ;
     RECT  5.115 5.737 5.67 5.809 ;
     RECT  14.22 5.453 14.922 5.881 ;
     RECT  14.184 5.881 14.922 5.981 ;
     RECT  2.304 5.809 5.67 6.035 ;
     RECT  7.815 2.413 8.097 6.115 ;
     RECT  6.444 6.091 6.462 6.139 ;
     RECT  7.815 6.115 8.262 6.151 ;
     RECT  7.236 6.151 8.262 6.269 ;
     RECT  11.736 5.693 12.618 6.269 ;
     RECT  9.576 0.523 9.594 6.277 ;
     RECT  11.736 6.269 12.33 6.539 ;
     RECT  8.892 6.277 9.594 6.575 ;
     RECT  11.736 6.539 11.754 6.611 ;
     RECT  6.12 6.139 6.462 6.655 ;
     RECT  7.236 6.269 8.097 6.655 ;
     RECT  2.304 6.035 5.397 6.809 ;
     RECT  10.515 2.413 10.797 6.817 ;
     RECT  14.184 5.981 14.238 7.051 ;
     RECT  13.644 7.051 14.238 7.088 ;
     RECT  6.12 6.655 8.097 7.349 ;
     RECT  9.036 6.575 9.594 7.393 ;
     RECT  10.515 6.817 11.538 7.465 ;
     RECT  6.12 7.349 6.138 7.655 ;
     RECT  2.304 6.809 3.978 7.735 ;
     RECT  8.928 7.393 9.594 7.735 ;
     RECT  10.515 7.465 11.79 7.735 ;
     RECT  7.416 7.349 8.097 7.771 ;
     RECT  14.22 7.088 14.238 7.861 ;
     RECT  2.304 7.735 4.122 7.867 ;
     RECT  4.86 6.809 5.397 7.867 ;
     RECT  14.22 7.861 14.274 7.867 ;
     RECT  8.928 7.735 11.79 7.889 ;
     RECT  2.304 7.867 5.397 7.925 ;
     RECT  10.515 7.889 11.79 7.925 ;
     RECT  11.592 7.925 11.79 8.005 ;
     RECT  11.592 8.005 12.402 8.041 ;
     RECT  11.592 8.041 12.474 8.195 ;
     RECT  14.22 7.867 14.31 8.267 ;
     RECT  7.416 7.771 8.154 8.275 ;
     RECT  7.308 8.275 8.154 8.311 ;
     RECT  8.928 7.889 9.702 8.437 ;
     RECT  6.48 8.311 8.154 8.491 ;
     RECT  6.228 8.491 8.154 8.525 ;
     RECT  4.86 7.925 5.397 8.539 ;
     RECT  6.228 8.525 8.097 8.539 ;
     RECT  2.304 7.925 3.978 8.699 ;
     RECT  8.892 8.437 9.702 8.699 ;
     RECT  8.892 8.699 9.45 8.735 ;
     RECT  3.492 8.699 3.978 8.779 ;
     RECT  4.86 8.539 8.097 8.779 ;
     RECT  14.22 8.267 14.238 8.851 ;
     RECT  10.515 7.925 10.797 8.941 ;
     RECT  11.628 8.195 12.186 8.941 ;
     RECT  3.492 8.779 8.097 8.969 ;
     RECT  10.515 8.941 12.186 9.085 ;
     RECT  10.515 9.085 12.618 9.239 ;
     RECT  2.304 8.699 2.697 9.275 ;
     RECT  6.264 8.969 8.097 9.481 ;
     RECT  13.68 8.851 14.238 9.481 ;
     RECT  6.264 9.481 8.262 9.517 ;
     RECT  9.036 8.735 9.45 9.517 ;
     RECT  6.264 9.517 9.45 9.533 ;
     RECT  13.644 9.481 14.238 9.533 ;
     RECT  10.515 9.239 12.15 9.545 ;
     RECT  2.415 9.275 2.697 9.691 ;
     RECT  3.492 8.969 5.397 9.691 ;
     RECT  2.415 9.691 5.397 9.787 ;
     RECT  6.264 9.533 8.097 9.787 ;
     RECT  8.892 9.533 9.45 9.815 ;
     RECT  2.415 9.787 8.097 10.027 ;
     RECT  2.34 10.027 8.097 10.049 ;
     RECT  10.515 9.545 12.006 10.049 ;
     RECT  2.34 10.049 5.397 10.085 ;
     RECT  14.22 9.533 14.238 10.315 ;
     RECT  14.184 10.315 14.238 10.319 ;
     RECT  6.48 10.049 8.097 10.589 ;
     RECT  13.068 10.471 13.086 10.637 ;
     RECT  9.036 9.815 9.45 10.705 ;
     RECT  14.184 10.319 14.202 10.831 ;
     RECT  2.415 10.085 4.05 10.843 ;
     RECT  7.416 10.589 8.097 10.843 ;
     RECT  4.932 10.085 5.397 10.867 ;
     RECT  6.228 10.831 6.246 10.867 ;
     RECT  4.932 10.867 6.246 10.877 ;
     RECT  13.644 10.831 14.202 10.877 ;
     RECT  2.304 10.843 4.05 10.895 ;
     RECT  2.415 10.895 4.05 10.975 ;
     RECT  8.892 10.705 9.45 11.003 ;
     RECT  2.415 10.975 4.122 11.371 ;
     RECT  4.932 10.877 6.102 11.371 ;
     RECT  14.22 11.101 14.238 11.371 ;
     RECT  14.22 11.371 14.958 11.453 ;
     RECT  7.416 10.843 8.154 11.551 ;
     RECT  2.415 11.371 6.102 11.611 ;
     RECT  2.415 11.611 6.498 11.669 ;
     RECT  9.036 11.003 9.45 11.785 ;
     RECT  10.515 10.049 11.646 11.785 ;
     RECT  7.308 11.551 8.154 11.911 ;
     RECT  8.892 11.785 9.45 11.911 ;
     RECT  2.415 11.669 6.066 11.981 ;
     RECT  7.308 11.911 9.45 11.981 ;
     RECT  7.308 11.981 8.154 12.083 ;
     RECT  8.892 11.981 9.45 12.083 ;
     RECT  7.308 12.083 8.097 12.217 ;
     RECT  2.415 11.981 5.742 12.235 ;
     RECT  14.22 11.453 14.238 12.451 ;
     RECT  0.54 12.487 0.558 12.557 ;
     RECT  14.22 12.451 14.958 12.557 ;
     RECT  10.515 11.785 11.79 12.631 ;
     RECT  6.84 12.217 8.097 12.715 ;
     RECT  2.34 12.235 5.742 12.785 ;
     RECT  4.86 12.785 5.742 12.829 ;
     RECT  6.48 12.715 8.097 12.829 ;
     RECT  9.036 12.083 9.45 12.865 ;
     RECT  10.515 12.631 12.042 12.991 ;
     RECT  2.34 12.785 4.122 13.051 ;
     RECT  4.86 12.829 8.097 13.055 ;
     RECT  2.304 13.051 4.122 13.531 ;
     RECT  4.86 13.055 5.742 13.531 ;
     RECT  14.22 12.557 14.238 13.531 ;
     RECT  14.22 13.531 14.958 13.603 ;
     RECT  13.644 13.603 14.958 13.661 ;
     RECT  10.515 12.991 12.402 13.675 ;
     RECT  6.48 13.055 8.097 13.711 ;
     RECT  8.892 12.865 9.45 13.711 ;
     RECT  2.304 13.531 5.742 13.981 ;
     RECT  6.48 13.711 9.45 13.981 ;
     RECT  10.515 13.675 12.654 14.099 ;
     RECT  2.304 13.981 9.45 14.189 ;
     RECT  14.22 13.661 14.958 14.189 ;
     RECT  2.412 14.189 9.45 14.207 ;
     RECT  7.308 14.207 9.45 14.243 ;
     RECT  10.515 14.099 12.402 14.369 ;
     RECT  14.22 14.189 14.238 14.443 ;
     RECT  13.788 14.443 14.238 14.549 ;
     RECT  11.736 14.369 12.402 14.909 ;
     RECT  2.412 14.207 6.498 14.945 ;
     RECT  2.412 14.945 4.086 14.971 ;
     RECT  11.736 14.909 11.754 14.981 ;
     RECT  5.115 14.945 6.498 15.053 ;
     RECT  7.308 14.243 8.097 15.061 ;
     RECT  9.036 14.243 9.45 15.061 ;
     RECT  6.624 15.061 8.097 15.179 ;
     RECT  9.036 15.061 9.558 15.295 ;
     RECT  8.856 15.295 9.558 15.331 ;
     RECT  10.515 14.369 10.797 15.331 ;
     RECT  8.856 15.331 10.797 15.449 ;
     RECT  14.22 14.549 14.238 15.547 ;
     RECT  12.6 15.601 12.618 15.755 ;
     RECT  5.115 15.053 5.814 15.835 ;
     RECT  2.304 14.971 4.086 15.871 ;
     RECT  4.824 15.835 5.814 15.871 ;
     RECT  10.515 15.449 10.797 15.871 ;
     RECT  11.52 15.295 11.538 15.871 ;
     RECT  13.644 15.547 14.238 15.899 ;
     RECT  2.304 15.871 5.814 15.997 ;
     RECT  2.304 15.997 5.886 16.025 ;
     RECT  4.824 16.025 5.886 16.141 ;
     RECT  6.66 15.179 8.097 16.141 ;
     RECT  10.515 15.871 11.682 16.141 ;
     RECT  4.824 16.141 8.097 16.259 ;
     RECT  10.515 16.141 12.042 16.259 ;
     RECT  9.036 15.449 9.558 16.375 ;
     RECT  8.928 16.375 9.558 16.529 ;
     RECT  4.824 16.259 6.606 16.541 ;
     RECT  11.628 16.259 12.042 16.601 ;
     RECT  11.736 16.601 12.042 16.645 ;
     RECT  11.736 16.645 12.618 16.799 ;
     RECT  2.304 16.025 4.086 16.879 ;
     RECT  4.824 16.541 6.462 16.879 ;
     RECT  14.22 15.899 14.238 16.891 ;
     RECT  7.416 16.259 8.097 17.077 ;
     RECT  2.304 16.879 6.462 17.105 ;
     RECT  11.736 16.799 12.474 17.105 ;
     RECT  2.34 17.105 6.462 17.117 ;
     RECT  7.272 17.077 8.097 17.375 ;
     RECT  9.036 16.529 9.558 17.455 ;
     RECT  7.416 17.375 8.097 17.491 ;
     RECT  8.928 17.455 9.558 17.491 ;
     RECT  7.416 17.491 9.558 17.609 ;
     RECT  11.736 17.105 12.222 17.761 ;
     RECT  14.22 16.891 14.958 17.789 ;
     RECT  2.34 17.117 6.174 17.915 ;
     RECT  3.42 17.915 6.174 17.951 ;
     RECT  11.52 17.761 12.222 17.951 ;
     RECT  2.34 17.915 2.697 17.995 ;
     RECT  3.816 17.951 6.174 18.121 ;
     RECT  7.416 17.609 8.262 18.157 ;
     RECT  3.816 18.121 6.246 18.187 ;
     RECT  10.515 16.259 10.797 18.193 ;
     RECT  11.52 17.951 11.97 18.193 ;
     RECT  7.272 18.157 8.262 18.427 ;
     RECT  9.036 17.609 9.558 18.427 ;
     RECT  3.816 18.187 6.462 18.499 ;
     RECT  7.272 18.427 9.558 18.499 ;
     RECT  3.816 18.499 9.558 18.689 ;
     RECT  2.304 17.995 2.697 18.697 ;
     RECT  3.816 18.689 6.462 18.697 ;
     RECT  10.515 18.193 11.97 18.797 ;
     RECT  10.515 18.797 11.79 18.959 ;
     RECT  2.304 18.697 6.462 19.265 ;
     RECT  4.86 19.265 6.462 19.499 ;
     RECT  7.2 18.689 9.558 19.579 ;
     RECT  6.84 19.579 9.558 19.651 ;
     RECT  10.515 18.959 11.682 19.651 ;
     RECT  6.84 19.651 11.682 19.769 ;
     RECT  6.84 19.769 8.658 19.841 ;
     RECT  0.144 19.819 0.162 19.949 ;
     RECT  2.34 19.265 4.086 20.039 ;
     RECT  3.816 20.039 4.086 20.191 ;
     RECT  4.86 19.499 5.814 20.191 ;
     RECT  2.34 20.039 3.042 20.203 ;
     RECT  3.816 20.191 5.814 20.281 ;
     RECT  10.515 19.769 11.682 20.281 ;
     RECT  3.816 20.281 6.462 20.345 ;
     RECT  4.86 20.345 6.462 20.659 ;
     RECT  7.272 19.841 8.658 20.659 ;
     RECT  4.86 20.659 8.658 20.695 ;
     RECT  9.54 19.769 9.558 20.695 ;
     RECT  14.22 17.789 14.238 20.731 ;
     RECT  10.515 20.281 11.754 20.821 ;
     RECT  12.6 20.731 12.618 20.821 ;
     RECT  2.304 20.203 3.042 20.827 ;
     RECT  3.816 20.345 4.086 20.827 ;
     RECT  4.86 20.695 9.558 20.849 ;
     RECT  4.86 20.849 8.658 20.921 ;
     RECT  10.515 20.821 12.618 20.921 ;
     RECT  13.644 20.731 14.238 21.029 ;
     RECT  0.144 20.923 0.162 21.053 ;
     RECT  2.304 20.827 4.086 21.271 ;
     RECT  4.86 20.921 6.462 21.271 ;
     RECT  2.304 21.271 6.462 21.425 ;
     RECT  12.6 20.921 12.618 21.461 ;
     RECT  5.115 21.425 6.462 21.643 ;
     RECT  7.2 20.921 8.658 21.643 ;
     RECT  5.115 21.643 8.658 21.775 ;
     RECT  9.54 20.849 9.558 21.775 ;
     RECT  10.515 20.921 11.61 21.775 ;
     RECT  5.115 21.775 9.558 21.929 ;
     RECT  10.515 21.775 11.646 21.929 ;
     RECT  11.592 21.929 11.646 22.045 ;
     RECT  2.304 21.425 4.086 22.315 ;
     RECT  5.115 21.929 8.658 22.315 ;
     RECT  11.592 22.045 11.718 22.351 ;
     RECT  11.592 22.351 12.006 22.469 ;
     RECT  9.54 21.929 9.558 22.585 ;
     RECT  2.304 22.315 8.658 22.589 ;
     RECT  14.22 21.029 14.238 22.651 ;
     RECT  6.624 22.589 8.658 22.739 ;
     RECT  9.54 22.585 9.594 22.783 ;
     RECT  6.84 22.739 8.658 22.855 ;
     RECT  9.54 22.783 9.702 22.855 ;
     RECT  12.456 22.621 12.474 22.891 ;
     RECT  14.184 22.651 14.238 22.939 ;
     RECT  11.592 22.469 11.61 22.981 ;
     RECT  6.84 22.855 9.702 23.009 ;
     RECT  9.54 23.009 9.594 23.045 ;
     RECT  12.456 22.891 12.51 23.045 ;
     RECT  10.515 21.929 10.797 23.125 ;
     RECT  11.52 22.981 11.61 23.125 ;
     RECT  13.572 22.939 14.238 23.189 ;
     RECT  2.304 22.589 5.814 23.371 ;
     RECT  10.515 23.125 11.61 23.431 ;
     RECT  12.456 23.045 12.474 23.431 ;
     RECT  6.84 23.009 8.658 23.557 ;
     RECT  10.515 23.431 12.474 23.657 ;
     RECT  2.304 23.371 5.886 23.701 ;
     RECT  6.66 23.557 8.658 23.701 ;
     RECT  12.456 23.657 12.474 23.855 ;
     RECT  2.304 23.701 8.658 23.899 ;
     RECT  9.576 23.045 9.594 23.899 ;
     RECT  13.644 23.189 14.238 23.927 ;
     RECT  2.304 23.899 9.594 23.933 ;
     RECT  8.856 23.933 9.594 24.089 ;
     RECT  0.144 24.283 0.162 24.413 ;
     RECT  12.6 24.331 12.618 24.431 ;
     RECT  10.515 23.657 11.682 24.745 ;
     RECT  10.515 24.745 11.754 24.899 ;
     RECT  2.304 23.933 8.097 24.979 ;
     RECT  2.304 24.979 8.262 25.051 ;
     RECT  9 24.089 9.594 25.051 ;
     RECT  2.304 25.051 9.594 25.169 ;
     RECT  8.928 25.169 9.594 25.205 ;
     RECT  10.515 24.899 11.682 25.825 ;
     RECT  2.304 25.169 8.154 26.093 ;
     RECT  9.036 25.205 9.594 26.095 ;
     RECT  14.22 23.927 14.238 26.249 ;
     RECT  10.515 25.825 11.754 26.329 ;
     RECT  12.636 26.095 12.654 26.329 ;
     RECT  10.515 26.329 12.654 26.491 ;
     RECT  2.304 26.093 5.742 26.627 ;
     RECT  10.515 26.491 13.086 26.663 ;
     RECT  4.824 26.627 5.742 26.765 ;
     RECT  6.48 26.093 8.097 26.789 ;
     RECT  14.94 26.761 14.958 26.813 ;
     RECT  7.056 26.789 8.097 26.905 ;
     RECT  8.856 26.095 9.594 26.905 ;
     RECT  7.056 26.905 9.594 27.167 ;
     RECT  7.056 27.167 8.298 27.203 ;
     RECT  9.036 27.167 9.594 27.301 ;
     RECT  10.515 26.663 12.546 27.301 ;
     RECT  2.304 26.627 4.086 27.355 ;
     RECT  9.036 27.301 12.546 27.365 ;
     RECT  9.036 27.365 11.574 27.599 ;
     RECT  2.304 27.355 4.158 27.751 ;
     RECT  4.896 26.765 5.742 27.751 ;
     RECT  14.22 27.019 14.238 27.841 ;
     RECT  2.304 27.751 6.138 27.931 ;
     RECT  7.056 27.203 8.097 27.931 ;
     RECT  2.304 27.931 8.154 28.021 ;
     RECT  12.6 27.913 12.618 28.139 ;
     RECT  13.68 27.841 14.238 28.157 ;
     RECT  2.304 28.021 8.262 28.175 ;
     RECT  2.415 28.175 8.262 28.291 ;
     RECT  9.036 27.599 9.594 28.291 ;
     RECT  2.415 28.291 9.594 28.381 ;
     RECT  10.515 27.599 11.538 28.381 ;
     RECT  2.415 28.381 11.538 28.445 ;
     RECT  9.036 28.445 11.538 28.525 ;
     RECT  9.036 28.525 11.682 28.679 ;
     RECT  2.415 28.445 8.262 29.069 ;
     RECT  5.115 29.069 8.262 29.227 ;
     RECT  9.036 28.679 9.594 29.227 ;
     RECT  2.415 29.069 4.194 29.497 ;
     RECT  5.115 29.227 9.594 29.525 ;
     RECT  9.036 29.525 9.594 29.605 ;
     RECT  10.515 28.679 11.682 29.605 ;
     RECT  9.036 29.605 11.682 29.731 ;
     RECT  14.22 28.157 14.238 29.755 ;
     RECT  2.304 29.497 4.194 29.795 ;
     RECT  9.036 29.731 12.294 29.795 ;
     RECT  4.176 29.795 4.194 30.109 ;
     RECT  5.115 29.525 8.154 30.109 ;
     RECT  4.176 30.109 8.154 30.173 ;
     RECT  10.26 29.795 12.294 30.299 ;
     RECT  9.036 29.795 9.234 30.371 ;
     RECT  10.515 30.299 12.294 30.371 ;
     RECT  13.644 29.755 14.238 30.371 ;
     RECT  5.115 30.173 8.154 30.379 ;
     RECT  9.036 30.371 9.054 30.379 ;
     RECT  2.304 29.795 3.438 30.577 ;
     RECT  4.176 30.173 4.266 30.577 ;
     RECT  2.304 30.577 4.266 30.839 ;
     RECT  4.032 30.839 4.266 30.875 ;
     RECT  2.304 30.839 3.294 30.893 ;
     RECT  10.515 30.371 12.222 30.911 ;
     RECT  4.212 30.875 4.266 30.919 ;
     RECT  5.115 30.379 9.054 30.919 ;
     RECT  4.212 30.919 9.054 31.117 ;
     RECT  4.212 31.117 9.27 31.261 ;
     RECT  10.515 30.911 11.754 31.261 ;
     RECT  4.212 31.261 11.754 31.277 ;
     RECT  0.144 31.225 0.162 31.469 ;
     RECT  9.792 31.277 11.754 31.649 ;
     RECT  4.212 31.277 9.054 31.657 ;
     RECT  2.415 30.893 3.294 31.675 ;
     RECT  2.304 31.675 3.294 31.685 ;
     RECT  14.22 30.371 14.238 31.709 ;
     RECT  4.068 31.657 9.054 31.801 ;
     RECT  10.515 31.649 11.754 31.801 ;
     RECT  10.515 31.801 12.042 31.891 ;
     RECT  3.42 31.801 9.054 31.919 ;
     RECT  2.304 31.685 2.697 31.955 ;
     RECT  4.068 31.919 9.054 31.955 ;
     RECT  10.515 31.891 12.618 31.991 ;
     RECT  14.94 31.891 14.958 31.997 ;
     RECT  4.536 31.955 9.054 32.035 ;
     RECT  4.536 32.035 9.198 32.261 ;
     RECT  6.228 32.261 9.198 32.369 ;
     RECT  13.86 32.251 13.878 32.539 ;
     RECT  13.644 32.539 13.878 32.701 ;
     RECT  7.308 32.369 9.198 32.729 ;
     RECT  4.536 32.261 5.397 32.737 ;
     RECT  2.412 31.955 2.697 32.765 ;
     RECT  7.38 32.729 9.198 32.765 ;
     RECT  3.492 32.737 3.51 32.773 ;
     RECT  4.356 32.737 5.397 32.773 ;
     RECT  13.644 32.701 14.238 32.813 ;
     RECT  10.515 31.991 12.294 32.845 ;
     RECT  2.415 32.765 2.697 32.881 ;
     RECT  3.492 32.773 5.397 32.881 ;
     RECT  10.515 32.845 12.582 32.999 ;
     RECT  2.415 32.881 5.397 33.043 ;
     RECT  6.228 32.369 6.462 33.043 ;
     RECT  7.416 32.765 9.198 33.043 ;
     RECT  2.415 33.043 6.462 33.053 ;
     RECT  11.664 32.999 12.582 33.071 ;
     RECT  13.644 32.813 13.806 33.341 ;
     RECT  13.788 33.341 13.806 33.449 ;
     RECT  11.736 33.071 12.582 33.539 ;
     RECT  11.736 33.539 11.754 33.611 ;
     RECT  4.068 33.053 6.462 33.629 ;
     RECT  7.416 33.043 9.702 33.655 ;
     RECT  7.308 33.655 9.702 33.809 ;
     RECT  12.636 33.655 12.654 33.809 ;
     RECT  2.415 33.053 3.114 33.883 ;
     RECT  4.068 33.629 6.246 33.917 ;
     RECT  2.34 33.883 3.114 33.961 ;
     RECT  4.068 33.917 6.21 33.961 ;
     RECT  10.515 32.999 10.797 33.961 ;
     RECT  7.416 33.809 9.702 34.079 ;
     RECT  8.964 34.079 9.198 34.115 ;
     RECT  2.34 33.961 6.21 34.171 ;
     RECT  2.304 34.171 6.21 34.349 ;
     RECT  12.6 34.321 12.618 34.421 ;
     RECT  4.824 34.349 6.21 34.493 ;
     RECT  5.004 34.493 6.21 34.619 ;
     RECT  10.515 33.961 11.502 34.619 ;
     RECT  7.416 34.079 8.097 34.735 ;
     RECT  5.115 34.619 6.21 34.795 ;
     RECT  7.308 34.735 8.097 34.925 ;
     RECT  7.416 34.925 8.097 34.933 ;
     RECT  8.964 34.115 9.162 34.933 ;
     RECT  5.115 34.795 6.462 35.021 ;
     RECT  2.304 34.349 3.978 35.275 ;
     RECT  11.592 34.735 11.682 35.275 ;
     RECT  0.144 34.735 0.162 35.309 ;
     RECT  5.115 35.021 5.886 35.371 ;
     RECT  11.592 35.275 11.79 35.429 ;
     RECT  2.304 35.275 4.122 35.465 ;
     RECT  10.515 34.619 10.797 35.545 ;
     RECT  11.592 35.429 11.682 35.545 ;
     RECT  3.528 35.465 4.122 35.581 ;
     RECT  4.86 35.371 5.886 35.581 ;
     RECT  7.416 34.933 9.162 35.699 ;
     RECT  3.528 35.581 5.886 35.779 ;
     RECT  3.528 35.779 6.246 35.815 ;
     RECT  3.528 35.815 6.714 35.969 ;
     RECT  3.528 35.969 6.462 36.005 ;
     RECT  7.815 35.699 9.162 36.121 ;
     RECT  7.815 36.121 9.378 36.239 ;
     RECT  10.515 35.545 11.682 36.239 ;
     RECT  2.304 35.465 2.697 36.391 ;
     RECT  3.528 36.005 4.086 36.391 ;
     RECT  2.304 36.391 4.086 36.689 ;
     RECT  7.815 36.239 9.162 36.859 ;
     RECT  4.86 36.005 6.462 36.887 ;
     RECT  7.416 36.859 9.162 36.895 ;
     RECT  14.22 33.583 14.238 36.895 ;
     RECT  3.672 36.689 4.086 36.931 ;
     RECT  4.86 36.887 5.742 36.931 ;
     RECT  7.308 36.895 9.162 36.931 ;
     RECT  14.184 36.895 14.238 36.941 ;
     RECT  3.672 36.931 5.742 37.085 ;
     RECT  10.515 36.239 11.538 37.291 ;
     RECT  10.515 37.291 11.754 37.391 ;
     RECT  2.304 36.689 2.697 37.429 ;
     RECT  3.672 37.085 4.122 37.429 ;
     RECT  6.624 36.931 9.162 37.499 ;
     RECT  2.304 37.429 4.122 37.589 ;
     RECT  4.86 37.085 5.742 37.741 ;
     RECT  4.86 37.741 6.498 38.045 ;
     RECT  10.515 37.391 11.538 38.137 ;
     RECT  7.236 37.499 9.162 38.281 ;
     RECT  7.236 38.281 9.594 38.399 ;
     RECT  7.236 38.399 9.09 38.435 ;
     RECT  7.236 38.435 8.19 38.443 ;
     RECT  2.304 37.589 4.05 38.515 ;
     RECT  10.515 38.137 11.61 38.515 ;
     RECT  2.304 38.515 4.122 38.669 ;
     RECT  6.84 38.443 8.19 38.741 ;
     RECT  4.86 38.045 5.778 38.911 ;
     RECT  7.308 38.741 8.19 39.209 ;
     RECT  7.416 39.209 8.19 39.217 ;
     RECT  8.928 38.435 9.09 39.217 ;
     RECT  7.416 39.217 9.09 39.253 ;
     RECT  10.515 38.515 11.682 39.451 ;
     RECT  7.416 39.253 9.702 39.479 ;
     RECT  2.304 38.669 3.942 39.595 ;
     RECT  2.304 39.595 4.122 39.749 ;
     RECT  4.86 38.911 6.498 39.749 ;
     RECT  5.004 39.749 6.498 40.019 ;
     RECT  10.515 39.451 11.754 40.019 ;
     RECT  7.416 39.479 9.09 40.135 ;
     RECT  6.48 40.019 6.498 40.171 ;
     RECT  7.308 40.135 9.09 40.171 ;
     RECT  10.515 40.019 11.646 40.289 ;
     RECT  6.48 40.171 9.09 40.361 ;
     RECT  8.82 40.361 9.09 40.441 ;
     RECT  6.48 40.361 8.097 40.469 ;
     RECT  8.82 40.441 9.486 40.559 ;
     RECT  8.82 40.559 9.09 40.595 ;
     RECT  4.248 39.865 4.266 40.639 ;
     RECT  2.304 39.749 3.438 40.675 ;
     RECT  4.176 40.639 4.266 40.675 ;
     RECT  2.304 40.675 4.266 40.747 ;
     RECT  5.115 40.019 5.706 40.747 ;
     RECT  11.592 40.289 11.646 40.945 ;
     RECT  2.304 40.747 5.706 40.981 ;
     RECT  6.48 40.469 6.498 40.981 ;
     RECT  11.592 40.945 11.682 41.071 ;
     RECT  2.304 40.981 6.498 41.135 ;
     RECT  2.304 41.135 5.397 41.171 ;
     RECT  8.928 40.595 9.09 41.243 ;
     RECT  10.515 40.289 10.797 41.251 ;
     RECT  11.592 41.071 11.754 41.251 ;
     RECT  6.264 41.135 6.498 41.369 ;
     RECT  8.928 41.243 9.018 41.377 ;
     RECT  7.272 40.469 8.097 41.413 ;
     RECT  6.84 41.413 8.097 41.549 ;
     RECT  8.892 41.377 9.018 41.675 ;
     RECT  10.515 41.251 11.754 41.881 ;
     RECT  5.115 41.171 5.397 41.917 ;
     RECT  2.304 41.171 4.194 41.989 ;
     RECT  5.115 41.917 5.742 41.989 ;
     RECT  10.515 41.881 12.006 42.025 ;
     RECT  10.515 42.025 12.618 42.179 ;
     RECT  2.304 41.989 5.742 42.187 ;
     RECT  7.344 41.549 8.097 42.295 ;
     RECT  14.22 36.941 14.238 42.379 ;
     RECT  9 41.675 9.018 42.457 ;
     RECT  10.515 42.179 12.474 42.485 ;
     RECT  2.304 42.187 6.462 42.529 ;
     RECT  13.608 42.379 14.238 42.557 ;
     RECT  2.304 42.529 6.498 42.565 ;
     RECT  2.268 42.565 6.498 42.701 ;
     RECT  10.515 42.485 11.898 42.719 ;
     RECT  8.892 42.457 9.018 42.727 ;
     RECT  2.304 42.701 6.498 42.997 ;
     RECT  7.308 42.295 8.097 42.997 ;
     RECT  2.304 42.997 8.097 43.259 ;
     RECT  7.308 43.259 8.097 43.267 ;
     RECT  8.892 42.727 9.126 43.267 ;
     RECT  7.308 43.267 9.126 43.367 ;
     RECT  14.22 42.557 14.238 43.529 ;
     RECT  10.515 42.719 11.754 43.681 ;
     RECT  12.528 43.645 12.546 43.681 ;
     RECT  7.308 43.367 8.874 43.709 ;
     RECT  10.515 43.681 12.546 43.843 ;
     RECT  14.94 43.843 14.958 44.045 ;
     RECT  10.515 43.843 12.618 44.069 ;
     RECT  2.304 43.259 6.462 44.077 ;
     RECT  7.308 43.709 8.097 44.077 ;
     RECT  2.304 44.077 8.097 44.299 ;
     RECT  13.644 43.771 13.662 44.299 ;
     RECT  2.268 44.299 8.097 44.375 ;
     RECT  4.86 44.375 8.097 44.653 ;
     RECT  8.856 43.709 8.874 44.653 ;
     RECT  4.86 44.653 8.874 44.725 ;
     RECT  10.515 44.069 12.078 44.995 ;
     RECT  13.644 44.299 14.238 45.115 ;
     RECT  4.86 44.725 8.91 45.149 ;
     RECT  9.9 44.995 12.654 45.149 ;
     RECT  2.304 44.375 4.122 45.229 ;
     RECT  4.86 45.149 6.462 45.229 ;
     RECT  13.572 45.115 14.238 45.329 ;
     RECT  2.304 45.229 6.462 45.419 ;
     RECT  2.304 45.419 4.302 45.455 ;
     RECT  5.112 45.419 6.462 45.491 ;
     RECT  5.112 45.491 6.246 45.689 ;
     RECT  7.308 45.149 8.91 45.689 ;
     RECT  10.515 45.149 12.654 45.689 ;
     RECT  14.184 45.329 14.238 45.725 ;
     RECT  10.515 45.689 11.97 45.761 ;
     RECT  7.416 45.689 8.91 45.805 ;
     RECT  7.416 45.805 9.054 46.103 ;
     RECT  9.036 46.103 9.054 46.111 ;
     RECT  9.036 46.111 9.702 46.229 ;
     RECT  2.304 45.455 4.122 46.265 ;
     RECT  9.036 46.229 9.558 46.265 ;
     RECT  2.415 46.265 4.122 46.309 ;
     RECT  5.112 45.689 6.138 46.309 ;
     RECT  13.068 46.219 13.086 46.337 ;
     RECT  10.515 45.761 11.394 46.499 ;
     RECT  7.416 46.103 8.19 46.507 ;
     RECT  2.415 46.309 6.138 46.535 ;
     RECT  5.115 46.535 6.138 46.651 ;
     RECT  7.236 46.507 8.19 46.651 ;
     RECT  5.115 46.651 8.19 46.769 ;
     RECT  7.236 46.769 8.19 46.805 ;
     RECT  7.416 46.805 8.19 46.885 ;
     RECT  9.036 46.265 9.054 46.885 ;
     RECT  7.416 46.885 9.054 47.183 ;
     RECT  9.036 47.183 9.054 47.191 ;
     RECT  9.036 47.191 9.774 47.272 ;
     RECT  10.515 46.499 10.797 47.272 ;
     RECT  14.22 45.725 14.238 47.281 ;
     RECT  9.036 47.272 10.797 47.309 ;
     RECT  9.036 47.309 9.666 47.345 ;
     RECT  14.22 47.281 14.958 47.357 ;
     RECT  11.664 46.615 11.682 47.425 ;
     RECT  10.515 47.309 10.797 47.551 ;
     RECT  2.415 46.535 4.122 47.611 ;
     RECT  5.115 46.769 6.462 47.611 ;
     RECT  7.416 47.183 8.262 47.731 ;
     RECT  2.415 47.611 6.462 47.848 ;
     RECT  2.304 47.848 6.462 47.849 ;
     RECT  10.515 47.551 10.818 47.857 ;
     RECT  11.664 47.425 11.754 47.857 ;
     RECT  7.308 47.731 8.262 47.885 ;
     RECT  7.416 47.885 8.262 47.965 ;
     RECT  9.036 47.345 9.054 47.965 ;
     RECT  10.515 47.857 11.754 47.965 ;
     RECT  7.416 47.965 9.054 48.119 ;
     RECT  10.515 47.965 11.826 48.119 ;
     RECT  2.304 47.849 4.086 48.173 ;
     RECT  8.892 48.119 9.054 48.263 ;
     RECT  14.22 47.357 14.238 48.361 ;
     RECT  2.415 48.173 4.086 48.389 ;
     RECT  11.664 48.119 11.826 48.631 ;
     RECT  12.564 48.271 12.582 48.631 ;
     RECT  11.664 48.631 12.582 48.659 ;
     RECT  5.115 47.849 6.462 48.667 ;
     RECT  11.736 48.659 12.582 48.695 ;
     RECT  14.184 48.361 14.238 48.715 ;
     RECT  4.824 48.667 6.462 48.731 ;
     RECT  11.736 48.695 12.186 48.731 ;
     RECT  13.644 48.715 14.238 48.767 ;
     RECT  7.416 48.119 8.154 48.811 ;
     RECT  2.415 48.389 3.834 48.955 ;
     RECT  7.308 48.811 8.154 48.965 ;
     RECT  2.304 48.955 3.834 49.315 ;
     RECT  7.416 48.965 8.154 49.351 ;
     RECT  8.928 48.263 9.054 49.351 ;
     RECT  2.304 49.315 4.086 49.469 ;
     RECT  5.115 48.731 6.462 49.771 ;
     RECT  2.304 49.469 3.834 49.811 ;
     RECT  4.824 49.771 6.462 49.811 ;
     RECT  11.736 48.731 12.042 49.811 ;
     RECT  7.416 49.351 9.054 49.891 ;
     RECT  5.004 49.811 6.462 50.009 ;
     RECT  7.308 49.891 9.054 50.045 ;
     RECT  7.416 50.045 9.054 50.081 ;
     RECT  12.168 49.855 12.402 50.125 ;
     RECT  5.115 50.009 6.462 50.279 ;
     RECT  12.168 50.125 12.654 50.279 ;
     RECT  12.168 50.279 12.186 50.351 ;
     RECT  8.892 50.081 9.054 50.423 ;
     RECT  2.415 49.811 3.834 50.557 ;
     RECT  7.416 50.081 8.154 50.573 ;
     RECT  2.415 50.557 4.086 50.827 ;
     RECT  2.304 50.827 4.086 50.855 ;
     RECT  11.736 50.791 11.754 50.891 ;
     RECT  5.115 50.279 5.886 50.923 ;
     RECT  7.416 50.573 8.097 50.971 ;
     RECT  6.804 50.971 8.097 51.097 ;
     RECT  4.824 50.923 5.886 51.149 ;
     RECT  11.628 51.061 11.646 51.161 ;
     RECT  6.768 51.097 8.097 51.307 ;
     RECT  9.036 50.423 9.054 51.475 ;
     RECT  6.768 51.307 8.154 51.511 ;
     RECT  8.928 51.475 9.054 51.511 ;
     RECT  6.768 51.511 9.054 51.629 ;
     RECT  2.304 50.855 3.834 51.637 ;
     RECT  10.515 48.119 10.797 51.673 ;
     RECT  4.824 51.149 5.85 51.677 ;
     RECT  14.22 48.767 14.238 51.691 ;
     RECT  2.304 51.637 4.086 51.935 ;
     RECT  6.768 51.629 8.262 51.979 ;
     RECT  12.636 52.015 12.654 52.051 ;
     RECT  6.624 51.979 8.262 52.141 ;
     RECT  12.456 52.051 12.654 52.169 ;
     RECT  4.824 51.677 5.814 52.411 ;
     RECT  6.588 52.141 8.262 52.445 ;
     RECT  4.824 52.411 5.85 52.459 ;
     RECT  13.788 51.691 14.238 52.507 ;
     RECT  7.272 52.445 8.262 52.555 ;
     RECT  9.036 51.629 9.054 52.555 ;
     RECT  10.515 51.673 11.466 52.681 ;
     RECT  12.456 52.169 12.474 52.681 ;
     RECT  7.272 52.555 9.054 52.709 ;
     RECT  2.304 51.935 3.978 52.717 ;
     RECT  10.515 52.681 12.474 52.745 ;
     RECT  10.515 52.745 11.79 52.781 ;
     RECT  13.572 52.507 14.238 52.889 ;
     RECT  10.515 52.781 11.754 53.051 ;
     RECT  2.304 52.717 4.086 53.131 ;
     RECT  4.824 52.459 6.462 53.131 ;
     RECT  2.304 53.131 6.462 53.371 ;
     RECT  7.272 52.709 8.262 53.371 ;
     RECT  2.304 53.371 8.262 53.519 ;
     RECT  2.304 53.519 8.154 53.597 ;
     RECT  14.22 52.889 14.238 53.611 ;
     RECT  9.036 52.709 9.054 53.635 ;
     RECT  2.304 53.597 8.097 53.789 ;
     RECT  2.304 53.789 5.922 53.825 ;
     RECT  12.276 53.761 12.294 53.861 ;
     RECT  13.644 53.611 14.238 53.861 ;
     RECT  10.515 53.051 11.538 53.905 ;
     RECT  10.515 53.905 11.61 54.059 ;
     RECT  12.6 53.905 12.618 54.059 ;
     RECT  2.304 53.825 5.886 54.095 ;
     RECT  3.6 54.095 5.886 54.329 ;
     RECT  6.804 53.789 8.097 54.401 ;
     RECT  8.928 53.635 9.054 54.481 ;
     RECT  5.076 54.329 5.886 54.571 ;
     RECT  10.515 54.059 11.178 54.679 ;
     RECT  7.416 54.401 8.097 54.715 ;
     RECT  8.892 54.481 9.054 54.743 ;
     RECT  7.416 54.715 8.154 54.751 ;
     RECT  8.892 54.743 8.982 54.751 ;
     RECT  10.224 54.679 11.178 54.841 ;
     RECT  2.304 54.095 2.697 54.859 ;
     RECT  3.6 54.329 4.086 54.859 ;
     RECT  10.224 54.841 11.79 54.869 ;
     RECT  7.416 54.751 8.982 54.905 ;
     RECT  0.144 54.445 0.162 55.037 ;
     RECT  5.076 54.571 6.246 55.147 ;
     RECT  7.416 54.905 8.154 55.147 ;
     RECT  2.304 54.859 4.086 55.175 ;
     RECT  5.076 55.147 8.154 55.243 ;
     RECT  3.816 55.175 4.086 55.255 ;
     RECT  4.824 55.243 8.154 55.255 ;
     RECT  3.816 55.255 8.154 55.445 ;
     RECT  10.515 54.869 11.79 55.651 ;
     RECT  8.964 54.905 8.982 55.831 ;
     RECT  2.304 55.175 2.697 55.915 ;
     RECT  3.816 55.445 4.05 55.915 ;
     RECT  10.515 55.651 12.222 55.921 ;
     RECT  8.928 55.831 8.982 55.985 ;
     RECT  10.515 55.921 12.33 56.021 ;
     RECT  0.144 56.107 0.162 56.285 ;
     RECT  2.304 55.915 4.05 56.371 ;
     RECT  5.115 55.445 5.814 56.371 ;
     RECT  6.624 55.445 8.154 56.371 ;
     RECT  8.964 55.985 8.982 56.641 ;
     RECT  2.304 56.371 8.154 56.759 ;
     RECT  7.272 56.759 8.154 56.795 ;
     RECT  8.964 56.641 9.414 56.911 ;
     RECT  7.416 56.795 8.154 57.001 ;
     RECT  8.928 56.911 9.414 57.001 ;
     RECT  10.515 56.021 11.646 57.001 ;
     RECT  7.416 57.001 9.414 57.053 ;
     RECT  8.928 57.053 9.414 57.065 ;
     RECT  10.515 57.001 11.754 57.101 ;
     RECT  8.964 57.065 9.414 57.335 ;
     RECT  10.515 57.101 11.682 57.569 ;
     RECT  7.416 57.053 8.19 57.577 ;
     RECT  2.304 56.759 6.498 57.605 ;
     RECT  4.824 57.605 6.498 57.721 ;
     RECT  7.272 57.577 8.19 57.721 ;
     RECT  4.824 57.721 8.19 57.883 ;
     RECT  8.964 57.335 8.982 57.883 ;
     RECT  11.592 57.569 11.682 57.955 ;
     RECT  11.592 57.955 11.754 58.225 ;
     RECT  11.592 58.225 11.826 58.379 ;
     RECT  14.22 53.861 14.238 58.555 ;
     RECT  4.824 57.883 8.982 58.649 ;
     RECT  0.144 58.555 0.162 58.685 ;
     RECT  4.824 58.649 6.498 58.991 ;
     RECT  7.308 58.649 8.982 59.063 ;
     RECT  2.304 57.605 4.05 59.071 ;
     RECT  4.824 58.991 6.066 59.071 ;
     RECT  10.515 57.569 10.797 59.071 ;
     RECT  14.184 58.555 14.238 59.131 ;
     RECT  10.224 59.071 10.797 59.189 ;
     RECT  2.304 59.071 6.066 59.213 ;
     RECT  7.815 59.063 8.982 59.213 ;
     RECT  8.856 59.213 8.982 59.225 ;
     RECT  12.564 58.081 12.582 59.233 ;
     RECT  8.964 59.225 8.982 59.261 ;
     RECT  11.736 58.379 11.754 59.341 ;
     RECT  12.564 59.233 12.618 59.341 ;
     RECT  11.736 59.341 12.618 59.431 ;
     RECT  11.556 59.431 12.618 59.459 ;
     RECT  14.184 59.131 14.958 59.459 ;
     RECT  2.304 59.213 6.03 59.495 ;
     RECT  11.556 59.459 11.574 59.531 ;
     RECT  3.6 59.495 3.618 59.729 ;
     RECT  4.464 59.495 6.03 59.729 ;
     RECT  14.22 59.459 14.958 59.729 ;
     RECT  2.304 59.495 2.697 59.765 ;
     RECT  4.464 59.729 5.397 59.765 ;
     RECT  12.348 59.459 12.618 59.765 ;
     RECT  14.94 59.729 14.958 59.999 ;
     RECT  12.348 59.765 12.366 60.035 ;
     RECT  2.415 59.765 2.697 62.387 ;
     RECT  5.115 59.765 5.397 62.387 ;
     RECT  7.815 59.213 8.097 62.387 ;
     RECT  10.515 59.189 10.797 62.387 ;
     RECT  2.415 62.387 2.505 62.657 ;
     RECT  5.115 62.387 5.205 62.657 ;
     RECT  7.815 62.387 7.905 62.657 ;
     RECT  10.515 62.387 10.605 62.657 ;
    LAYER M4 ;
     RECT  0.085 1.392 0.108 1.416 ;
     RECT  0.085 31.344 0.108 31.368 ;
     RECT  0.108 5.424 2.408 59.4 ;
     RECT  2.408 2.148 2.512 62.652 ;
     RECT  2.512 2.418 2.704 62.382 ;
     RECT  2.704 33.024 2.729 36.456 ;
     RECT  2.704 28.704 2.765 28.968 ;
     RECT  2.729 34.224 2.765 36.456 ;
     RECT  2.704 45.6 2.765 47.352 ;
     RECT  2.704 7.872 2.801 11.976 ;
     RECT  2.729 33.024 2.801 33.096 ;
     RECT  2.704 48.72 2.801 54.888 ;
     RECT  2.704 15.408 2.837 16.632 ;
     RECT  2.704 17.616 2.909 19.848 ;
     RECT  2.704 31.152 2.909 31.464 ;
     RECT  2.704 58.656 2.909 59.208 ;
     RECT  2.704 20.832 3.089 20.952 ;
     RECT  2.801 10.896 3.125 11.976 ;
     RECT  2.837 15.408 3.197 16.584 ;
     RECT  2.909 17.616 3.233 19.752 ;
     RECT  3.233 19.728 3.299 19.752 ;
     RECT  2.704 21.936 3.299 22.968 ;
     RECT  2.704 24.096 3.305 25.176 ;
     RECT  2.704 55.92 3.305 57.048 ;
     RECT  3.233 17.616 3.34 18.744 ;
     RECT  3.089 20.832 3.34 20.856 ;
     RECT  3.299 21.936 3.34 22.824 ;
     RECT  2.765 34.224 3.347 34.248 ;
     RECT  2.765 35.28 3.347 36.456 ;
     RECT  2.704 37.44 3.347 37.464 ;
     RECT  2.704 38.544 3.347 38.568 ;
     RECT  2.704 39.6 3.347 39.624 ;
     RECT  2.704 41.808 3.347 41.832 ;
     RECT  2.704 42.816 3.347 42.84 ;
     RECT  2.704 43.92 3.347 43.944 ;
     RECT  2.801 50.592 3.347 54.888 ;
     RECT  3.305 55.92 3.347 55.944 ;
     RECT  3.347 50.592 3.349 52.488 ;
     RECT  3.197 15.408 3.443 15.432 ;
     RECT  2.801 33.024 3.521 33.048 ;
     RECT  3.305 24.096 3.587 24.12 ;
     RECT  2.704 26.256 3.587 26.28 ;
     RECT  3.305 25.152 3.629 25.176 ;
     RECT  2.704 6.768 3.949 6.792 ;
     RECT  2.801 7.872 3.949 9.816 ;
     RECT  2.704 14.256 3.949 14.28 ;
     RECT  2.909 31.44 4.201 31.464 ;
     RECT  2.765 46.848 4.273 46.872 ;
     RECT  2.765 45.6 4.796 45.624 ;
     RECT  4.273 46.848 4.796 47.832 ;
     RECT  3.949 6.288 4.813 9.816 ;
     RECT  3.197 16.56 4.813 16.584 ;
     RECT  4.129 27.36 4.813 27.384 ;
     RECT  4.201 31.008 4.813 31.464 ;
     RECT  3.305 57.024 4.813 57.048 ;
     RECT  4.813 26.736 4.837 27.384 ;
     RECT  4.837 26.736 4.844 27.432 ;
     RECT  4.813 34.464 4.844 34.488 ;
     RECT  3.347 36.24 4.844 36.264 ;
     RECT  3.125 10.896 4.849 10.92 ;
     RECT  3.125 11.952 4.849 11.976 ;
     RECT  4.813 6.096 5.108 9.816 ;
     RECT  4.849 10.896 5.108 11.976 ;
     RECT  3.949 14.256 5.108 14.328 ;
     RECT  4.813 16.368 5.108 16.584 ;
     RECT  3.34 18 5.108 18.024 ;
     RECT  4.849 19.344 5.108 19.368 ;
     RECT  3.34 22.8 5.108 22.824 ;
     RECT  4.844 26.736 5.108 27.912 ;
     RECT  4.813 29.04 5.108 29.064 ;
     RECT  4.813 30.144 5.108 32.328 ;
     RECT  4.813 33.36 5.108 33.384 ;
     RECT  4.844 34.464 5.108 36.504 ;
     RECT  2.704 40.752 5.108 40.776 ;
     RECT  4.796 43.296 5.108 44.184 ;
     RECT  4.796 45.264 5.108 48.696 ;
     RECT  4.796 49.776 5.108 49.8 ;
     RECT  3.349 50.928 5.108 52.488 ;
     RECT  3.347 53.568 5.108 53.592 ;
     RECT  4.813 55.248 5.108 55.272 ;
     RECT  4.813 56.544 5.108 57.048 ;
     RECT  3.949 58.128 5.108 58.152 ;
     RECT  2.909 59.184 5.108 59.208 ;
     RECT  5.108 2.148 5.212 62.652 ;
     RECT  5.212 2.418 5.404 62.382 ;
     RECT  5.404 46.8 5.603 46.872 ;
     RECT  5.404 39.888 5.717 39.912 ;
     RECT  5.404 50.16 5.717 55.416 ;
     RECT  5.404 40.992 5.761 41.016 ;
     RECT  5.404 16.368 5.897 16.584 ;
     RECT  5.404 8.496 6.005 9.816 ;
     RECT  5.404 56.448 6.113 58.152 ;
     RECT  5.404 6.096 6.149 6.312 ;
     RECT  5.404 7.44 6.149 7.464 ;
     RECT  5.717 51.12 6.323 55.416 ;
     RECT  5.404 14.352 6.371 14.376 ;
     RECT  5.404 35.856 6.389 36.264 ;
     RECT  5.404 21.648 6.421 21.816 ;
     RECT  5.404 23.376 6.421 23.4 ;
     RECT  6.389 35.856 6.421 36.504 ;
     RECT  6.005 8.496 6.428 9.528 ;
     RECT  5.404 10.848 6.428 11.976 ;
     RECT  5.897 16.512 6.428 16.584 ;
     RECT  6.428 18.192 6.433 18.216 ;
     RECT  5.404 19.344 6.433 19.368 ;
     RECT  5.404 27.36 6.433 27.384 ;
     RECT  5.404 31.44 6.433 31.656 ;
     RECT  6.421 34.992 6.433 36.504 ;
     RECT  6.421 21.504 6.467 23.4 ;
     RECT  6.149 6.096 6.473 6.264 ;
     RECT  6.433 34.8 6.473 36.504 ;
     RECT  5.603 46.8 6.473 46.824 ;
     RECT  6.323 55.392 6.473 55.416 ;
     RECT  6.421 15.024 6.508 15.048 ;
     RECT  6.433 18.192 6.508 19.368 ;
     RECT  6.421 20.4 6.508 20.424 ;
     RECT  6.467 21.504 6.508 22.584 ;
     RECT  6.473 34.8 6.508 36.264 ;
     RECT  6.113 56.448 6.509 58.008 ;
     RECT  6.428 7.248 6.515 7.272 ;
     RECT  6.428 8.352 6.515 9.528 ;
     RECT  6.428 10.512 6.515 12.744 ;
     RECT  6.428 13.776 6.515 13.8 ;
     RECT  6.428 16.512 6.515 17.112 ;
     RECT  6.508 18.192 6.515 18.84 ;
     RECT  6.428 33.6 6.515 33.624 ;
     RECT  6.508 35.856 6.515 36.264 ;
     RECT  6.428 42.192 6.515 42.216 ;
     RECT  6.515 18.816 6.517 18.84 ;
     RECT  6.433 31.344 6.517 32.232 ;
     RECT  6.508 34.8 6.517 34.824 ;
     RECT  5.404 30.24 6.537 30.264 ;
     RECT  6.469 38.016 6.563 38.04 ;
     RECT  6.469 39.072 6.563 39.096 ;
     RECT  6.433 26.064 6.565 26.088 ;
     RECT  6.508 21.648 6.645 21.672 ;
     RECT  6.323 51.648 6.833 53.496 ;
     RECT  6.433 27.36 7.436 27.96 ;
     RECT  7.549 30.864 7.621 30.888 ;
     RECT  6.473 6.144 7.808 6.264 ;
     RECT  6.515 8.496 7.808 9.528 ;
     RECT  6.515 10.848 7.808 10.872 ;
     RECT  6.515 11.952 7.808 11.976 ;
     RECT  7.477 14.208 7.808 14.232 ;
     RECT  6.515 16.512 7.808 16.536 ;
     RECT  6.565 25.632 7.808 26.088 ;
     RECT  7.436 27.216 7.808 27.96 ;
     RECT  7.621 30.864 7.808 30.984 ;
     RECT  6.517 32.208 7.808 32.232 ;
     RECT  6.515 36.24 7.808 36.264 ;
     RECT  6.469 40.08 7.808 40.104 ;
     RECT  7.477 43.536 7.808 43.56 ;
     RECT  5.404 44.832 7.808 44.856 ;
     RECT  6.833 51.648 7.808 53.4 ;
     RECT  6.509 57.024 7.808 58.008 ;
     RECT  5.404 59.184 7.808 59.208 ;
     RECT  7.808 2.148 7.912 62.652 ;
     RECT  7.912 2.418 8.104 62.382 ;
     RECT  8.104 25.2 8.165 26.088 ;
     RECT  8.104 27.936 8.165 27.96 ;
     RECT  8.104 8.496 8.243 9.624 ;
     RECT  8.104 10.848 8.243 10.872 ;
     RECT  8.104 13.056 8.243 13.08 ;
     RECT  8.104 14.208 8.243 14.232 ;
     RECT  8.104 15.216 8.243 15.24 ;
     RECT  8.104 16.272 8.243 16.296 ;
     RECT  8.104 17.376 8.243 17.4 ;
     RECT  8.104 18.528 8.243 18.552 ;
     RECT  8.104 19.536 8.243 19.56 ;
     RECT  8.104 20.592 8.243 20.616 ;
     RECT  8.104 21.696 8.243 21.72 ;
     RECT  8.104 23.904 8.243 23.928 ;
     RECT  8.165 25.2 8.243 25.224 ;
     RECT  8.104 34.176 8.243 34.2 ;
     RECT  8.104 35.184 8.243 36.264 ;
     RECT  8.104 39.312 8.243 40.44 ;
     RECT  8.104 41.472 8.243 41.496 ;
     RECT  8.104 42.576 8.243 43.56 ;
     RECT  8.104 49.488 8.243 49.512 ;
     RECT  8.104 50.544 8.243 53.592 ;
     RECT  8.104 54.72 8.243 54.744 ;
     RECT  8.243 35.904 8.245 36.264 ;
     RECT  8.104 45.12 8.245 45.144 ;
     RECT  8.243 9.504 8.273 9.528 ;
     RECT  8.104 11.952 8.273 11.976 ;
     RECT  8.245 36.24 8.273 36.264 ;
     RECT  8.243 51.648 8.273 53.4 ;
     RECT  8.104 57.024 8.273 57.048 ;
     RECT  8.104 59.184 8.273 59.208 ;
     RECT  8.104 30.96 8.813 31.272 ;
     RECT  8.813 31.248 9.281 31.272 ;
     RECT  9.565 0.528 9.731 0.552 ;
     RECT  9.565 47.28 10.508 47.304 ;
     RECT  8.273 53.088 10.508 53.112 ;
     RECT  10.508 2.148 10.612 62.652 ;
     RECT  10.612 2.418 10.804 62.382 ;
     RECT  10.804 53.088 11.225 53.112 ;
     RECT  13.057 10.608 13.633 10.632 ;
     RECT  13.561 22.944 13.633 22.968 ;
     RECT  13.561 45.12 13.633 45.144 ;
     RECT  13.633 9.504 13.669 9.528 ;
     RECT  13.633 13.632 13.777 13.656 ;
     RECT  13.633 32.544 13.777 33.096 ;
     RECT  13.561 52.512 13.777 52.536 ;
     RECT  13.777 32.544 13.849 33.384 ;
     RECT  13.093 5.664 14.173 5.688 ;
     RECT  13.633 7.056 14.173 7.08 ;
     RECT  13.669 8.928 14.173 9.528 ;
     RECT  13.633 10.608 14.173 10.872 ;
     RECT  13.633 22.944 14.173 23.784 ;
     RECT  13.633 43.776 14.173 45.144 ;
     RECT  13.057 46.224 14.173 46.248 ;
     RECT  13.633 48.72 14.173 48.744 ;
     RECT  14.173 5.664 14.209 7.08 ;
     RECT  14.173 8.928 14.209 10.872 ;
     RECT  13.777 13.632 14.209 14.472 ;
     RECT  13.633 15.552 14.209 15.576 ;
     RECT  13.633 20.736 14.209 20.76 ;
     RECT  14.173 22.656 14.209 23.784 ;
     RECT  13.057 26.496 14.209 26.52 ;
     RECT  13.669 28.128 14.209 28.152 ;
     RECT  13.633 29.76 14.209 30.36 ;
     RECT  13.849 32.256 14.209 33.384 ;
     RECT  14.173 36.912 14.209 36.936 ;
     RECT  13.597 42.384 14.209 42.408 ;
     RECT  14.173 43.776 14.209 46.248 ;
     RECT  14.173 48.432 14.209 48.744 ;
     RECT  13.777 51.696 14.209 52.536 ;
     RECT  13.633 53.616 14.209 53.64 ;
     RECT  14.173 58.56 14.209 58.872 ;
     RECT  14.209 5.664 14.929 59.4 ;
     RECT  14.929 5.424 15.036 59.4 ;
    LAYER M5 ;
     RECT  0.192 1.285 0.216 1.381 ;
     RECT  0.096 1.381 0.216 1.427 ;
     RECT  2.4 2.137 2.52 2.151 ;
     RECT  5.1 2.137 5.22 2.151 ;
     RECT  7.8 2.137 7.92 2.151 ;
     RECT  10.5 2.137 10.62 2.151 ;
     RECT  2.4 2.151 2.712 7.861 ;
     RECT  7.8 2.151 8.112 8.485 ;
     RECT  2.4 7.861 3.528 8.819 ;
     RECT  5.1 2.151 5.412 9.493 ;
     RECT  6.48 7.237 6.504 9.493 ;
     RECT  7.8 8.485 8.232 10.883 ;
     RECT  2.4 8.819 3.336 10.931 ;
     RECT  7.8 10.883 8.112 13.045 ;
     RECT  5.1 9.493 6.504 13.811 ;
     RECT  2.4 10.931 2.712 14.245 ;
     RECT  5.1 13.811 6.36 15.013 ;
     RECT  2.4 14.245 3.432 15.443 ;
     RECT  5.1 15.013 6.456 17.077 ;
     RECT  2.4 15.443 2.712 17.605 ;
     RECT  5.1 17.077 6.504 18.851 ;
     RECT  5.1 18.851 6.456 21.637 ;
     RECT  7.8 13.045 8.232 21.731 ;
     RECT  5.1 21.637 6.6 23.411 ;
     RECT  7.8 21.731 8.112 23.893 ;
     RECT  2.4 17.605 3.288 24.085 ;
     RECT  7.8 23.893 8.232 25.235 ;
     RECT  6.576 23.411 6.6 25.621 ;
     RECT  7.8 25.235 8.112 25.621 ;
     RECT  6.576 25.621 8.112 25.667 ;
     RECT  2.4 24.085 3.576 26.291 ;
     RECT  5.1 23.411 5.592 26.725 ;
     RECT  6.816 25.667 8.112 27.395 ;
     RECT  4.848 26.725 5.592 27.443 ;
     RECT  7.488 27.395 8.112 27.971 ;
     RECT  4.896 27.443 5.592 30.229 ;
     RECT  0.096 1.427 0.12 31.333 ;
     RECT  0.096 31.333 0.264 31.379 ;
     RECT  4.896 30.229 6.504 31.379 ;
     RECT  0.24 31.379 0.264 31.475 ;
     RECT  2.4 26.291 2.712 33.013 ;
     RECT  4.896 31.379 5.688 33.589 ;
     RECT  7.8 27.971 8.112 34.165 ;
     RECT  2.4 33.013 3.336 34.259 ;
     RECT  4.896 33.589 6.504 34.835 ;
     RECT  2.4 34.259 2.712 35.269 ;
     RECT  4.896 34.835 6.456 35.845 ;
     RECT  7.8 34.165 8.232 35.939 ;
     RECT  4.896 35.845 6.504 36.515 ;
     RECT  5.1 36.515 6.504 38.005 ;
     RECT  5.1 38.005 6.552 39.107 ;
     RECT  7.8 35.939 8.112 39.301 ;
     RECT  5.1 39.107 6.504 39.923 ;
     RECT  5.1 39.923 5.412 40.981 ;
     RECT  6.48 39.923 6.504 40.981 ;
     RECT  5.1 40.981 6.504 42.227 ;
     RECT  5.1 42.227 5.736 43.285 ;
     RECT  2.4 35.269 3.336 43.955 ;
     RECT  4.848 43.285 5.736 44.867 ;
     RECT  7.8 39.301 8.232 45.155 ;
     RECT  7.8 45.155 8.112 49.477 ;
     RECT  4.848 44.867 5.592 49.811 ;
     RECT  2.4 43.955 2.712 50.581 ;
     RECT  5.1 49.811 5.592 51.109 ;
     RECT  7.8 49.477 8.232 51.347 ;
     RECT  7.8 51.347 8.112 53.557 ;
     RECT  7.8 53.557 8.232 54.755 ;
     RECT  5.1 51.109 6.312 56.579 ;
     RECT  2.4 50.581 3.336 57.059 ;
     RECT  2.4 57.059 2.712 62.649 ;
     RECT  5.1 56.579 5.412 62.649 ;
     RECT  7.8 54.755 8.112 62.649 ;
     RECT  10.5 2.151 10.812 62.649 ;
     RECT  2.4 62.649 2.52 62.663 ;
     RECT  5.1 62.649 5.22 62.663 ;
     RECT  7.8 62.649 7.92 62.663 ;
     RECT  10.5 62.649 10.62 62.663 ;
     RECT  5.412 7.237 6.48 9.493 ;
     RECT  6.504 7.237 7.8 13.811 ;
     RECT  6.36 13.811 7.8 15.013 ;
     RECT  6.456 15.013 7.8 17.077 ;
     RECT  6.504 17.077 7.8 18.851 ;
     RECT  6.456 18.851 7.8 21.637 ;
     RECT  6.6 21.637 7.8 25.621 ;
     RECT  5.592 23.411 6.576 25.667 ;
     RECT  3.576 24.085 5.1 26.291 ;
     RECT  5.592 25.667 6.816 27.395 ;
     RECT  4.848 26.291 5.1 26.725 ;
     RECT  6.504 30.229 7.8 31.379 ;
     RECT  6.504 33.589 7.8 34.835 ;
     RECT  2.712 34.259 3.336 35.269 ;
     RECT  6.456 34.835 7.8 35.845 ;
     RECT  6.504 35.845 7.8 38.005 ;
     RECT  6.552 38.005 7.8 39.107 ;
     RECT  6.504 39.107 7.8 42.227 ;
     RECT  5.412 39.923 6.48 40.981 ;
     RECT  3.336 43.285 4.848 43.955 ;
     RECT  6.312 51.109 7.8 56.579 ;
  END
END qwen_tx_rnes_r1
END LIBRARY
